VERSION 5.8 ;
BUSBITCHARS "[]" ;
DIVIDERCHAR "/" ;
UNITS
    DATABASE MICRONS 1000 ;
END UNITS

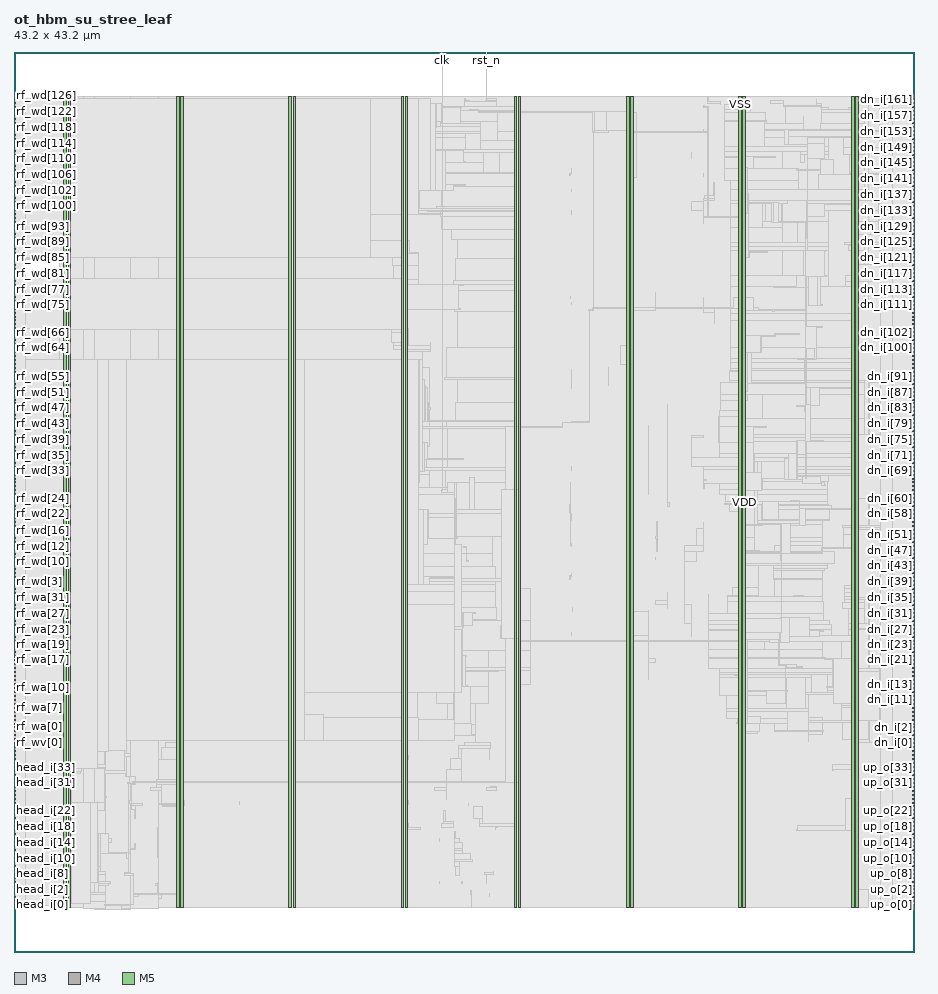
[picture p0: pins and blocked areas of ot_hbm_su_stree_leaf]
MACRO ot_hbm_su_stree_leaf
  FOREIGN ot_hbm_su_stree_leaf 0 0 ;
  CLASS BLOCK ;
  SIZE 43.2 BY 43.2 ;
  PIN clk
    DIRECTION INPUT ;
    USE SIGNAL ;
    PORT
      LAYER M3 ;
        RECT  20.52 43.162 20.538 43.2 ;
    END
  END clk
  PIN dn_i[0]
    DIRECTION INPUT ;
    USE SIGNAL ;
    PORT
      LAYER M4 ;
        RECT  43.116 10.032 43.2 10.056 ;
    END
  END dn_i[0]
  PIN dn_i[100]
    DIRECTION INPUT ;
    USE SIGNAL ;
    PORT
      LAYER M4 ;
        RECT  43.116 28.992 43.2 29.016 ;
    END
  END dn_i[100]
  PIN dn_i[101]
    DIRECTION INPUT ;
    USE SIGNAL ;
    PORT
      LAYER M4 ;
        RECT  43.116 29.184 43.2 29.208 ;
    END
  END dn_i[101]
  PIN dn_i[102]
    DIRECTION INPUT ;
    USE SIGNAL ;
    PORT
      LAYER M4 ;
        RECT  43.116 29.376 43.2 29.4 ;
    END
  END dn_i[102]
  PIN dn_i[103]
    DIRECTION INPUT ;
    USE SIGNAL ;
    PORT
      LAYER M4 ;
        RECT  43.116 29.568 43.2 29.592 ;
    END
  END dn_i[103]
  PIN dn_i[104]
    DIRECTION INPUT ;
    USE SIGNAL ;
    PORT
      LAYER M4 ;
        RECT  43.116 29.76 43.2 29.784 ;
    END
  END dn_i[104]
  PIN dn_i[105]
    DIRECTION INPUT ;
    USE SIGNAL ;
    PORT
      LAYER M4 ;
        RECT  43.116 29.952 43.2 29.976 ;
    END
  END dn_i[105]
  PIN dn_i[106]
    DIRECTION INPUT ;
    USE SIGNAL ;
    PORT
      LAYER M4 ;
        RECT  43.116 30.144 43.2 30.168 ;
    END
  END dn_i[106]
  PIN dn_i[107]
    DIRECTION INPUT ;
    USE SIGNAL ;
    PORT
      LAYER M4 ;
        RECT  43.116 30.336 43.2 30.36 ;
    END
  END dn_i[107]
  PIN dn_i[108]
    DIRECTION INPUT ;
    USE SIGNAL ;
    PORT
      LAYER M4 ;
        RECT  43.116 30.48 43.2 30.504 ;
    END
  END dn_i[108]
  PIN dn_i[109]
    DIRECTION INPUT ;
    USE SIGNAL ;
    PORT
      LAYER M4 ;
        RECT  43.116 30.672 43.2 30.696 ;
    END
  END dn_i[109]
  PIN dn_i[10]
    DIRECTION INPUT ;
    USE SIGNAL ;
    PORT
      LAYER M4 ;
        RECT  43.116 11.904 43.2 11.928 ;
    END
  END dn_i[10]
  PIN dn_i[110]
    DIRECTION INPUT ;
    USE SIGNAL ;
    PORT
      LAYER M4 ;
        RECT  43.116 30.864 43.2 30.888 ;
    END
  END dn_i[110]
  PIN dn_i[111]
    DIRECTION INPUT ;
    USE SIGNAL ;
    PORT
      LAYER M4 ;
        RECT  43.116 31.056 43.2 31.08 ;
    END
  END dn_i[111]
  PIN dn_i[112]
    DIRECTION INPUT ;
    USE SIGNAL ;
    PORT
      LAYER M4 ;
        RECT  43.116 31.248 43.2 31.272 ;
    END
  END dn_i[112]
  PIN dn_i[113]
    DIRECTION INPUT ;
    USE SIGNAL ;
    PORT
      LAYER M4 ;
        RECT  43.116 31.44 43.2 31.464 ;
    END
  END dn_i[113]
  PIN dn_i[114]
    DIRECTION INPUT ;
    USE SIGNAL ;
    PORT
      LAYER M4 ;
        RECT  43.116 31.632 43.2 31.656 ;
    END
  END dn_i[114]
  PIN dn_i[115]
    DIRECTION INPUT ;
    USE SIGNAL ;
    PORT
      LAYER M4 ;
        RECT  43.116 31.824 43.2 31.848 ;
    END
  END dn_i[115]
  PIN dn_i[116]
    DIRECTION INPUT ;
    USE SIGNAL ;
    PORT
      LAYER M4 ;
        RECT  43.116 32.016 43.2 32.04 ;
    END
  END dn_i[116]
  PIN dn_i[117]
    DIRECTION INPUT ;
    USE SIGNAL ;
    PORT
      LAYER M4 ;
        RECT  43.116 32.208 43.2 32.232 ;
    END
  END dn_i[117]
  PIN dn_i[118]
    DIRECTION INPUT ;
    USE SIGNAL ;
    PORT
      LAYER M4 ;
        RECT  43.116 32.4 43.2 32.424 ;
    END
  END dn_i[118]
  PIN dn_i[119]
    DIRECTION INPUT ;
    USE SIGNAL ;
    PORT
      LAYER M4 ;
        RECT  43.116 32.592 43.2 32.616 ;
    END
  END dn_i[119]
  PIN dn_i[11]
    DIRECTION INPUT ;
    USE SIGNAL ;
    PORT
      LAYER M4 ;
        RECT  43.116 12.096 43.2 12.12 ;
    END
  END dn_i[11]
  PIN dn_i[120]
    DIRECTION INPUT ;
    USE SIGNAL ;
    PORT
      LAYER M4 ;
        RECT  43.116 32.784 43.2 32.808 ;
    END
  END dn_i[120]
  PIN dn_i[121]
    DIRECTION INPUT ;
    USE SIGNAL ;
    PORT
      LAYER M4 ;
        RECT  43.116 32.976 43.2 33 ;
    END
  END dn_i[121]
  PIN dn_i[122]
    DIRECTION INPUT ;
    USE SIGNAL ;
    PORT
      LAYER M4 ;
        RECT  43.116 33.168 43.2 33.192 ;
    END
  END dn_i[122]
  PIN dn_i[123]
    DIRECTION INPUT ;
    USE SIGNAL ;
    PORT
      LAYER M4 ;
        RECT  43.116 33.36 43.2 33.384 ;
    END
  END dn_i[123]
  PIN dn_i[124]
    DIRECTION INPUT ;
    USE SIGNAL ;
    PORT
      LAYER M4 ;
        RECT  43.116 33.552 43.2 33.576 ;
    END
  END dn_i[124]
  PIN dn_i[125]
    DIRECTION INPUT ;
    USE SIGNAL ;
    PORT
      LAYER M4 ;
        RECT  43.116 33.744 43.2 33.768 ;
    END
  END dn_i[125]
  PIN dn_i[126]
    DIRECTION INPUT ;
    USE SIGNAL ;
    PORT
      LAYER M4 ;
        RECT  43.116 33.936 43.2 33.96 ;
    END
  END dn_i[126]
  PIN dn_i[127]
    DIRECTION INPUT ;
    USE SIGNAL ;
    PORT
      LAYER M4 ;
        RECT  43.116 34.128 43.2 34.152 ;
    END
  END dn_i[127]
  PIN dn_i[128]
    DIRECTION INPUT ;
    USE SIGNAL ;
    PORT
      LAYER M4 ;
        RECT  43.116 34.272 43.2 34.296 ;
    END
  END dn_i[128]
  PIN dn_i[129]
    DIRECTION INPUT ;
    USE SIGNAL ;
    PORT
      LAYER M4 ;
        RECT  43.116 34.464 43.2 34.488 ;
    END
  END dn_i[129]
  PIN dn_i[12]
    DIRECTION INPUT ;
    USE SIGNAL ;
    PORT
      LAYER M4 ;
        RECT  43.116 12.288 43.2 12.312 ;
    END
  END dn_i[12]
  PIN dn_i[130]
    DIRECTION INPUT ;
    USE SIGNAL ;
    PORT
      LAYER M4 ;
        RECT  43.116 34.656 43.2 34.68 ;
    END
  END dn_i[130]
  PIN dn_i[131]
    DIRECTION INPUT ;
    USE SIGNAL ;
    PORT
      LAYER M4 ;
        RECT  43.116 34.848 43.2 34.872 ;
    END
  END dn_i[131]
  PIN dn_i[132]
    DIRECTION INPUT ;
    USE SIGNAL ;
    PORT
      LAYER M4 ;
        RECT  43.116 35.04 43.2 35.064 ;
    END
  END dn_i[132]
  PIN dn_i[133]
    DIRECTION INPUT ;
    USE SIGNAL ;
    PORT
      LAYER M4 ;
        RECT  43.116 35.232 43.2 35.256 ;
    END
  END dn_i[133]
  PIN dn_i[134]
    DIRECTION INPUT ;
    USE SIGNAL ;
    PORT
      LAYER M4 ;
        RECT  43.116 35.424 43.2 35.448 ;
    END
  END dn_i[134]
  PIN dn_i[135]
    DIRECTION INPUT ;
    USE SIGNAL ;
    PORT
      LAYER M4 ;
        RECT  43.116 35.616 43.2 35.64 ;
    END
  END dn_i[135]
  PIN dn_i[136]
    DIRECTION INPUT ;
    USE SIGNAL ;
    PORT
      LAYER M4 ;
        RECT  43.116 35.808 43.2 35.832 ;
    END
  END dn_i[136]
  PIN dn_i[137]
    DIRECTION INPUT ;
    USE SIGNAL ;
    PORT
      LAYER M4 ;
        RECT  43.116 36 43.2 36.024 ;
    END
  END dn_i[137]
  PIN dn_i[138]
    DIRECTION INPUT ;
    USE SIGNAL ;
    PORT
      LAYER M4 ;
        RECT  43.116 36.192 43.2 36.216 ;
    END
  END dn_i[138]
  PIN dn_i[139]
    DIRECTION INPUT ;
    USE SIGNAL ;
    PORT
      LAYER M4 ;
        RECT  43.116 36.384 43.2 36.408 ;
    END
  END dn_i[139]
  PIN dn_i[13]
    DIRECTION INPUT ;
    USE SIGNAL ;
    PORT
      LAYER M4 ;
        RECT  43.116 12.48 43.2 12.504 ;
    END
  END dn_i[13]
  PIN dn_i[140]
    DIRECTION INPUT ;
    USE SIGNAL ;
    PORT
      LAYER M4 ;
        RECT  43.116 36.576 43.2 36.6 ;
    END
  END dn_i[140]
  PIN dn_i[141]
    DIRECTION INPUT ;
    USE SIGNAL ;
    PORT
      LAYER M4 ;
        RECT  43.116 36.768 43.2 36.792 ;
    END
  END dn_i[141]
  PIN dn_i[142]
    DIRECTION INPUT ;
    USE SIGNAL ;
    PORT
      LAYER M4 ;
        RECT  43.116 36.96 43.2 36.984 ;
    END
  END dn_i[142]
  PIN dn_i[143]
    DIRECTION INPUT ;
    USE SIGNAL ;
    PORT
      LAYER M4 ;
        RECT  43.116 37.152 43.2 37.176 ;
    END
  END dn_i[143]
  PIN dn_i[144]
    DIRECTION INPUT ;
    USE SIGNAL ;
    PORT
      LAYER M4 ;
        RECT  43.116 37.344 43.2 37.368 ;
    END
  END dn_i[144]
  PIN dn_i[145]
    DIRECTION INPUT ;
    USE SIGNAL ;
    PORT
      LAYER M4 ;
        RECT  43.116 37.536 43.2 37.56 ;
    END
  END dn_i[145]
  PIN dn_i[146]
    DIRECTION INPUT ;
    USE SIGNAL ;
    PORT
      LAYER M4 ;
        RECT  43.116 37.728 43.2 37.752 ;
    END
  END dn_i[146]
  PIN dn_i[147]
    DIRECTION INPUT ;
    USE SIGNAL ;
    PORT
      LAYER M4 ;
        RECT  43.116 37.92 43.2 37.944 ;
    END
  END dn_i[147]
  PIN dn_i[148]
    DIRECTION INPUT ;
    USE SIGNAL ;
    PORT
      LAYER M4 ;
        RECT  43.116 38.112 43.2 38.136 ;
    END
  END dn_i[148]
  PIN dn_i[149]
    DIRECTION INPUT ;
    USE SIGNAL ;
    PORT
      LAYER M4 ;
        RECT  43.116 38.256 43.2 38.28 ;
    END
  END dn_i[149]
  PIN dn_i[14]
    DIRECTION INPUT ;
    USE SIGNAL ;
    PORT
      LAYER M4 ;
        RECT  43.116 12.672 43.2 12.696 ;
    END
  END dn_i[14]
  PIN dn_i[150]
    DIRECTION INPUT ;
    USE SIGNAL ;
    PORT
      LAYER M4 ;
        RECT  43.116 38.448 43.2 38.472 ;
    END
  END dn_i[150]
  PIN dn_i[151]
    DIRECTION INPUT ;
    USE SIGNAL ;
    PORT
      LAYER M4 ;
        RECT  43.116 38.64 43.2 38.664 ;
    END
  END dn_i[151]
  PIN dn_i[152]
    DIRECTION INPUT ;
    USE SIGNAL ;
    PORT
      LAYER M4 ;
        RECT  43.116 38.832 43.2 38.856 ;
    END
  END dn_i[152]
  PIN dn_i[153]
    DIRECTION INPUT ;
    USE SIGNAL ;
    PORT
      LAYER M4 ;
        RECT  43.116 39.024 43.2 39.048 ;
    END
  END dn_i[153]
  PIN dn_i[154]
    DIRECTION INPUT ;
    USE SIGNAL ;
    PORT
      LAYER M4 ;
        RECT  43.116 39.216 43.2 39.24 ;
    END
  END dn_i[154]
  PIN dn_i[155]
    DIRECTION INPUT ;
    USE SIGNAL ;
    PORT
      LAYER M4 ;
        RECT  43.116 39.408 43.2 39.432 ;
    END
  END dn_i[155]
  PIN dn_i[156]
    DIRECTION INPUT ;
    USE SIGNAL ;
    PORT
      LAYER M4 ;
        RECT  43.116 39.6 43.2 39.624 ;
    END
  END dn_i[156]
  PIN dn_i[157]
    DIRECTION INPUT ;
    USE SIGNAL ;
    PORT
      LAYER M4 ;
        RECT  43.116 39.792 43.2 39.816 ;
    END
  END dn_i[157]
  PIN dn_i[158]
    DIRECTION INPUT ;
    USE SIGNAL ;
    PORT
      LAYER M4 ;
        RECT  43.116 39.984 43.2 40.008 ;
    END
  END dn_i[158]
  PIN dn_i[159]
    DIRECTION INPUT ;
    USE SIGNAL ;
    PORT
      LAYER M4 ;
        RECT  43.116 40.176 43.2 40.2 ;
    END
  END dn_i[159]
  PIN dn_i[15]
    DIRECTION INPUT ;
    USE SIGNAL ;
    PORT
      LAYER M4 ;
        RECT  43.116 12.864 43.2 12.888 ;
    END
  END dn_i[15]
  PIN dn_i[160]
    DIRECTION INPUT ;
    USE SIGNAL ;
    PORT
      LAYER M4 ;
        RECT  43.116 40.368 43.2 40.392 ;
    END
  END dn_i[160]
  PIN dn_i[161]
    DIRECTION INPUT ;
    USE SIGNAL ;
    PORT
      LAYER M4 ;
        RECT  43.116 40.56 43.2 40.584 ;
    END
  END dn_i[161]
  PIN dn_i[162]
    DIRECTION INPUT ;
    USE SIGNAL ;
    PORT
      LAYER M4 ;
        RECT  43.116 40.752 43.2 40.776 ;
    END
  END dn_i[162]
  PIN dn_i[163]
    DIRECTION INPUT ;
    USE SIGNAL ;
    PORT
      LAYER M4 ;
        RECT  43.116 40.944 43.2 40.968 ;
    END
  END dn_i[163]
  PIN dn_i[16]
    DIRECTION INPUT ;
    USE SIGNAL ;
    PORT
      LAYER M4 ;
        RECT  43.116 13.056 43.2 13.08 ;
    END
  END dn_i[16]
  PIN dn_i[17]
    DIRECTION INPUT ;
    USE SIGNAL ;
    PORT
      LAYER M4 ;
        RECT  43.116 13.248 43.2 13.272 ;
    END
  END dn_i[17]
  PIN dn_i[18]
    DIRECTION INPUT ;
    USE SIGNAL ;
    PORT
      LAYER M4 ;
        RECT  43.116 13.44 43.2 13.464 ;
    END
  END dn_i[18]
  PIN dn_i[19]
    DIRECTION INPUT ;
    USE SIGNAL ;
    PORT
      LAYER M4 ;
        RECT  43.116 13.632 43.2 13.656 ;
    END
  END dn_i[19]
  PIN dn_i[1]
    DIRECTION INPUT ;
    USE SIGNAL ;
    PORT
      LAYER M4 ;
        RECT  43.116 10.224 43.2 10.248 ;
    END
  END dn_i[1]
  PIN dn_i[20]
    DIRECTION INPUT ;
    USE SIGNAL ;
    PORT
      LAYER M4 ;
        RECT  43.116 13.824 43.2 13.848 ;
    END
  END dn_i[20]
  PIN dn_i[21]
    DIRECTION INPUT ;
    USE SIGNAL ;
    PORT
      LAYER M4 ;
        RECT  43.116 14.016 43.2 14.04 ;
    END
  END dn_i[21]
  PIN dn_i[22]
    DIRECTION INPUT ;
    USE SIGNAL ;
    PORT
      LAYER M4 ;
        RECT  43.116 14.208 43.2 14.232 ;
    END
  END dn_i[22]
  PIN dn_i[23]
    DIRECTION INPUT ;
    USE SIGNAL ;
    PORT
      LAYER M4 ;
        RECT  43.116 14.4 43.2 14.424 ;
    END
  END dn_i[23]
  PIN dn_i[24]
    DIRECTION INPUT ;
    USE SIGNAL ;
    PORT
      LAYER M4 ;
        RECT  43.116 14.592 43.2 14.616 ;
    END
  END dn_i[24]
  PIN dn_i[25]
    DIRECTION INPUT ;
    USE SIGNAL ;
    PORT
      LAYER M4 ;
        RECT  43.116 14.784 43.2 14.808 ;
    END
  END dn_i[25]
  PIN dn_i[26]
    DIRECTION INPUT ;
    USE SIGNAL ;
    PORT
      LAYER M4 ;
        RECT  43.116 14.928 43.2 14.952 ;
    END
  END dn_i[26]
  PIN dn_i[27]
    DIRECTION INPUT ;
    USE SIGNAL ;
    PORT
      LAYER M4 ;
        RECT  43.116 15.12 43.2 15.144 ;
    END
  END dn_i[27]
  PIN dn_i[28]
    DIRECTION INPUT ;
    USE SIGNAL ;
    PORT
      LAYER M4 ;
        RECT  43.116 15.312 43.2 15.336 ;
    END
  END dn_i[28]
  PIN dn_i[29]
    DIRECTION INPUT ;
    USE SIGNAL ;
    PORT
      LAYER M4 ;
        RECT  43.116 15.504 43.2 15.528 ;
    END
  END dn_i[29]
  PIN dn_i[2]
    DIRECTION INPUT ;
    USE SIGNAL ;
    PORT
      LAYER M4 ;
        RECT  43.116 10.416 43.2 10.44 ;
    END
  END dn_i[2]
  PIN dn_i[30]
    DIRECTION INPUT ;
    USE SIGNAL ;
    PORT
      LAYER M4 ;
        RECT  43.116 15.696 43.2 15.72 ;
    END
  END dn_i[30]
  PIN dn_i[31]
    DIRECTION INPUT ;
    USE SIGNAL ;
    PORT
      LAYER M4 ;
        RECT  43.116 15.888 43.2 15.912 ;
    END
  END dn_i[31]
  PIN dn_i[32]
    DIRECTION INPUT ;
    USE SIGNAL ;
    PORT
      LAYER M4 ;
        RECT  43.116 16.08 43.2 16.104 ;
    END
  END dn_i[32]
  PIN dn_i[33]
    DIRECTION INPUT ;
    USE SIGNAL ;
    PORT
      LAYER M4 ;
        RECT  43.116 16.272 43.2 16.296 ;
    END
  END dn_i[33]
  PIN dn_i[34]
    DIRECTION INPUT ;
    USE SIGNAL ;
    PORT
      LAYER M4 ;
        RECT  43.116 16.464 43.2 16.488 ;
    END
  END dn_i[34]
  PIN dn_i[35]
    DIRECTION INPUT ;
    USE SIGNAL ;
    PORT
      LAYER M4 ;
        RECT  43.116 16.656 43.2 16.68 ;
    END
  END dn_i[35]
  PIN dn_i[36]
    DIRECTION INPUT ;
    USE SIGNAL ;
    PORT
      LAYER M4 ;
        RECT  43.116 16.848 43.2 16.872 ;
    END
  END dn_i[36]
  PIN dn_i[37]
    DIRECTION INPUT ;
    USE SIGNAL ;
    PORT
      LAYER M4 ;
        RECT  43.116 17.04 43.2 17.064 ;
    END
  END dn_i[37]
  PIN dn_i[38]
    DIRECTION INPUT ;
    USE SIGNAL ;
    PORT
      LAYER M4 ;
        RECT  43.116 17.232 43.2 17.256 ;
    END
  END dn_i[38]
  PIN dn_i[39]
    DIRECTION INPUT ;
    USE SIGNAL ;
    PORT
      LAYER M4 ;
        RECT  43.116 17.424 43.2 17.448 ;
    END
  END dn_i[39]
  PIN dn_i[3]
    DIRECTION INPUT ;
    USE SIGNAL ;
    PORT
      LAYER M4 ;
        RECT  43.116 10.608 43.2 10.632 ;
    END
  END dn_i[3]
  PIN dn_i[40]
    DIRECTION INPUT ;
    USE SIGNAL ;
    PORT
      LAYER M4 ;
        RECT  43.116 17.616 43.2 17.64 ;
    END
  END dn_i[40]
  PIN dn_i[41]
    DIRECTION INPUT ;
    USE SIGNAL ;
    PORT
      LAYER M4 ;
        RECT  43.116 17.808 43.2 17.832 ;
    END
  END dn_i[41]
  PIN dn_i[42]
    DIRECTION INPUT ;
    USE SIGNAL ;
    PORT
      LAYER M4 ;
        RECT  43.116 18 43.2 18.024 ;
    END
  END dn_i[42]
  PIN dn_i[43]
    DIRECTION INPUT ;
    USE SIGNAL ;
    PORT
      LAYER M4 ;
        RECT  43.116 18.192 43.2 18.216 ;
    END
  END dn_i[43]
  PIN dn_i[44]
    DIRECTION INPUT ;
    USE SIGNAL ;
    PORT
      LAYER M4 ;
        RECT  43.116 18.384 43.2 18.408 ;
    END
  END dn_i[44]
  PIN dn_i[45]
    DIRECTION INPUT ;
    USE SIGNAL ;
    PORT
      LAYER M4 ;
        RECT  43.116 18.576 43.2 18.6 ;
    END
  END dn_i[45]
  PIN dn_i[46]
    DIRECTION INPUT ;
    USE SIGNAL ;
    PORT
      LAYER M4 ;
        RECT  43.116 18.72 43.2 18.744 ;
    END
  END dn_i[46]
  PIN dn_i[47]
    DIRECTION INPUT ;
    USE SIGNAL ;
    PORT
      LAYER M4 ;
        RECT  43.116 18.912 43.2 18.936 ;
    END
  END dn_i[47]
  PIN dn_i[48]
    DIRECTION INPUT ;
    USE SIGNAL ;
    PORT
      LAYER M4 ;
        RECT  43.116 19.104 43.2 19.128 ;
    END
  END dn_i[48]
  PIN dn_i[49]
    DIRECTION INPUT ;
    USE SIGNAL ;
    PORT
      LAYER M4 ;
        RECT  43.116 19.296 43.2 19.32 ;
    END
  END dn_i[49]
  PIN dn_i[4]
    DIRECTION INPUT ;
    USE SIGNAL ;
    PORT
      LAYER M4 ;
        RECT  43.116 10.8 43.2 10.824 ;
    END
  END dn_i[4]
  PIN dn_i[50]
    DIRECTION INPUT ;
    USE SIGNAL ;
    PORT
      LAYER M4 ;
        RECT  43.116 19.488 43.2 19.512 ;
    END
  END dn_i[50]
  PIN dn_i[51]
    DIRECTION INPUT ;
    USE SIGNAL ;
    PORT
      LAYER M4 ;
        RECT  43.116 19.68 43.2 19.704 ;
    END
  END dn_i[51]
  PIN dn_i[52]
    DIRECTION INPUT ;
    USE SIGNAL ;
    PORT
      LAYER M4 ;
        RECT  43.116 19.872 43.2 19.896 ;
    END
  END dn_i[52]
  PIN dn_i[53]
    DIRECTION INPUT ;
    USE SIGNAL ;
    PORT
      LAYER M4 ;
        RECT  43.116 20.064 43.2 20.088 ;
    END
  END dn_i[53]
  PIN dn_i[54]
    DIRECTION INPUT ;
    USE SIGNAL ;
    PORT
      LAYER M4 ;
        RECT  43.116 20.256 43.2 20.28 ;
    END
  END dn_i[54]
  PIN dn_i[55]
    DIRECTION INPUT ;
    USE SIGNAL ;
    PORT
      LAYER M4 ;
        RECT  43.116 20.448 43.2 20.472 ;
    END
  END dn_i[55]
  PIN dn_i[56]
    DIRECTION INPUT ;
    USE SIGNAL ;
    PORT
      LAYER M4 ;
        RECT  43.116 20.64 43.2 20.664 ;
    END
  END dn_i[56]
  PIN dn_i[57]
    DIRECTION INPUT ;
    USE SIGNAL ;
    PORT
      LAYER M4 ;
        RECT  43.116 20.832 43.2 20.856 ;
    END
  END dn_i[57]
  PIN dn_i[58]
    DIRECTION INPUT ;
    USE SIGNAL ;
    PORT
      LAYER M4 ;
        RECT  43.116 21.024 43.2 21.048 ;
    END
  END dn_i[58]
  PIN dn_i[59]
    DIRECTION INPUT ;
    USE SIGNAL ;
    PORT
      LAYER M4 ;
        RECT  43.116 21.216 43.2 21.24 ;
    END
  END dn_i[59]
  PIN dn_i[5]
    DIRECTION INPUT ;
    USE SIGNAL ;
    PORT
      LAYER M4 ;
        RECT  43.116 10.944 43.2 10.968 ;
    END
  END dn_i[5]
  PIN dn_i[60]
    DIRECTION INPUT ;
    USE SIGNAL ;
    PORT
      LAYER M4 ;
        RECT  43.116 21.408 43.2 21.432 ;
    END
  END dn_i[60]
  PIN dn_i[61]
    DIRECTION INPUT ;
    USE SIGNAL ;
    PORT
      LAYER M4 ;
        RECT  43.116 21.6 43.2 21.624 ;
    END
  END dn_i[61]
  PIN dn_i[62]
    DIRECTION INPUT ;
    USE SIGNAL ;
    PORT
      LAYER M4 ;
        RECT  43.116 21.792 43.2 21.816 ;
    END
  END dn_i[62]
  PIN dn_i[63]
    DIRECTION INPUT ;
    USE SIGNAL ;
    PORT
      LAYER M4 ;
        RECT  43.116 21.984 43.2 22.008 ;
    END
  END dn_i[63]
  PIN dn_i[64]
    DIRECTION INPUT ;
    USE SIGNAL ;
    PORT
      LAYER M4 ;
        RECT  43.116 22.176 43.2 22.2 ;
    END
  END dn_i[64]
  PIN dn_i[65]
    DIRECTION INPUT ;
    USE SIGNAL ;
    PORT
      LAYER M4 ;
        RECT  43.116 22.368 43.2 22.392 ;
    END
  END dn_i[65]
  PIN dn_i[66]
    DIRECTION INPUT ;
    USE SIGNAL ;
    PORT
      LAYER M4 ;
        RECT  43.116 22.56 43.2 22.584 ;
    END
  END dn_i[66]
  PIN dn_i[67]
    DIRECTION INPUT ;
    USE SIGNAL ;
    PORT
      LAYER M4 ;
        RECT  43.116 22.704 43.2 22.728 ;
    END
  END dn_i[67]
  PIN dn_i[68]
    DIRECTION INPUT ;
    USE SIGNAL ;
    PORT
      LAYER M4 ;
        RECT  43.116 22.896 43.2 22.92 ;
    END
  END dn_i[68]
  PIN dn_i[69]
    DIRECTION INPUT ;
    USE SIGNAL ;
    PORT
      LAYER M4 ;
        RECT  43.116 23.088 43.2 23.112 ;
    END
  END dn_i[69]
  PIN dn_i[6]
    DIRECTION INPUT ;
    USE SIGNAL ;
    PORT
      LAYER M4 ;
        RECT  43.116 11.136 43.2 11.16 ;
    END
  END dn_i[6]
  PIN dn_i[70]
    DIRECTION INPUT ;
    USE SIGNAL ;
    PORT
      LAYER M4 ;
        RECT  43.116 23.28 43.2 23.304 ;
    END
  END dn_i[70]
  PIN dn_i[71]
    DIRECTION INPUT ;
    USE SIGNAL ;
    PORT
      LAYER M4 ;
        RECT  43.116 23.472 43.2 23.496 ;
    END
  END dn_i[71]
  PIN dn_i[72]
    DIRECTION INPUT ;
    USE SIGNAL ;
    PORT
      LAYER M4 ;
        RECT  43.116 23.664 43.2 23.688 ;
    END
  END dn_i[72]
  PIN dn_i[73]
    DIRECTION INPUT ;
    USE SIGNAL ;
    PORT
      LAYER M4 ;
        RECT  43.116 23.856 43.2 23.88 ;
    END
  END dn_i[73]
  PIN dn_i[74]
    DIRECTION INPUT ;
    USE SIGNAL ;
    PORT
      LAYER M4 ;
        RECT  43.116 24.048 43.2 24.072 ;
    END
  END dn_i[74]
  PIN dn_i[75]
    DIRECTION INPUT ;
    USE SIGNAL ;
    PORT
      LAYER M4 ;
        RECT  43.116 24.24 43.2 24.264 ;
    END
  END dn_i[75]
  PIN dn_i[76]
    DIRECTION INPUT ;
    USE SIGNAL ;
    PORT
      LAYER M4 ;
        RECT  43.116 24.432 43.2 24.456 ;
    END
  END dn_i[76]
  PIN dn_i[77]
    DIRECTION INPUT ;
    USE SIGNAL ;
    PORT
      LAYER M4 ;
        RECT  43.116 24.624 43.2 24.648 ;
    END
  END dn_i[77]
  PIN dn_i[78]
    DIRECTION INPUT ;
    USE SIGNAL ;
    PORT
      LAYER M4 ;
        RECT  43.116 24.816 43.2 24.84 ;
    END
  END dn_i[78]
  PIN dn_i[79]
    DIRECTION INPUT ;
    USE SIGNAL ;
    PORT
      LAYER M4 ;
        RECT  43.116 25.008 43.2 25.032 ;
    END
  END dn_i[79]
  PIN dn_i[7]
    DIRECTION INPUT ;
    USE SIGNAL ;
    PORT
      LAYER M4 ;
        RECT  43.116 11.328 43.2 11.352 ;
    END
  END dn_i[7]
  PIN dn_i[80]
    DIRECTION INPUT ;
    USE SIGNAL ;
    PORT
      LAYER M4 ;
        RECT  43.116 25.2 43.2 25.224 ;
    END
  END dn_i[80]
  PIN dn_i[81]
    DIRECTION INPUT ;
    USE SIGNAL ;
    PORT
      LAYER M4 ;
        RECT  43.116 25.392 43.2 25.416 ;
    END
  END dn_i[81]
  PIN dn_i[82]
    DIRECTION INPUT ;
    USE SIGNAL ;
    PORT
      LAYER M4 ;
        RECT  43.116 25.584 43.2 25.608 ;
    END
  END dn_i[82]
  PIN dn_i[83]
    DIRECTION INPUT ;
    USE SIGNAL ;
    PORT
      LAYER M4 ;
        RECT  43.116 25.776 43.2 25.8 ;
    END
  END dn_i[83]
  PIN dn_i[84]
    DIRECTION INPUT ;
    USE SIGNAL ;
    PORT
      LAYER M4 ;
        RECT  43.116 25.968 43.2 25.992 ;
    END
  END dn_i[84]
  PIN dn_i[85]
    DIRECTION INPUT ;
    USE SIGNAL ;
    PORT
      LAYER M4 ;
        RECT  43.116 26.16 43.2 26.184 ;
    END
  END dn_i[85]
  PIN dn_i[86]
    DIRECTION INPUT ;
    USE SIGNAL ;
    PORT
      LAYER M4 ;
        RECT  43.116 26.352 43.2 26.376 ;
    END
  END dn_i[86]
  PIN dn_i[87]
    DIRECTION INPUT ;
    USE SIGNAL ;
    PORT
      LAYER M4 ;
        RECT  43.116 26.496 43.2 26.52 ;
    END
  END dn_i[87]
  PIN dn_i[88]
    DIRECTION INPUT ;
    USE SIGNAL ;
    PORT
      LAYER M4 ;
        RECT  43.116 26.688 43.2 26.712 ;
    END
  END dn_i[88]
  PIN dn_i[89]
    DIRECTION INPUT ;
    USE SIGNAL ;
    PORT
      LAYER M4 ;
        RECT  43.116 26.88 43.2 26.904 ;
    END
  END dn_i[89]
  PIN dn_i[8]
    DIRECTION INPUT ;
    USE SIGNAL ;
    PORT
      LAYER M4 ;
        RECT  43.116 11.52 43.2 11.544 ;
    END
  END dn_i[8]
  PIN dn_i[90]
    DIRECTION INPUT ;
    USE SIGNAL ;
    PORT
      LAYER M4 ;
        RECT  43.116 27.072 43.2 27.096 ;
    END
  END dn_i[90]
  PIN dn_i[91]
    DIRECTION INPUT ;
    USE SIGNAL ;
    PORT
      LAYER M4 ;
        RECT  43.116 27.264 43.2 27.288 ;
    END
  END dn_i[91]
  PIN dn_i[92]
    DIRECTION INPUT ;
    USE SIGNAL ;
    PORT
      LAYER M4 ;
        RECT  43.116 27.456 43.2 27.48 ;
    END
  END dn_i[92]
  PIN dn_i[93]
    DIRECTION INPUT ;
    USE SIGNAL ;
    PORT
      LAYER M4 ;
        RECT  43.116 27.648 43.2 27.672 ;
    END
  END dn_i[93]
  PIN dn_i[94]
    DIRECTION INPUT ;
    USE SIGNAL ;
    PORT
      LAYER M4 ;
        RECT  43.116 27.84 43.2 27.864 ;
    END
  END dn_i[94]
  PIN dn_i[95]
    DIRECTION INPUT ;
    USE SIGNAL ;
    PORT
      LAYER M4 ;
        RECT  43.116 28.032 43.2 28.056 ;
    END
  END dn_i[95]
  PIN dn_i[96]
    DIRECTION INPUT ;
    USE SIGNAL ;
    PORT
      LAYER M4 ;
        RECT  43.116 28.224 43.2 28.248 ;
    END
  END dn_i[96]
  PIN dn_i[97]
    DIRECTION INPUT ;
    USE SIGNAL ;
    PORT
      LAYER M4 ;
        RECT  43.116 28.416 43.2 28.44 ;
    END
  END dn_i[97]
  PIN dn_i[98]
    DIRECTION INPUT ;
    USE SIGNAL ;
    PORT
      LAYER M4 ;
        RECT  43.116 28.608 43.2 28.632 ;
    END
  END dn_i[98]
  PIN dn_i[99]
    DIRECTION INPUT ;
    USE SIGNAL ;
    PORT
      LAYER M4 ;
        RECT  43.116 28.8 43.2 28.824 ;
    END
  END dn_i[99]
  PIN dn_i[9]
    DIRECTION INPUT ;
    USE SIGNAL ;
    PORT
      LAYER M4 ;
        RECT  43.116 11.712 43.2 11.736 ;
    END
  END dn_i[9]
  PIN head_i[0]
    DIRECTION INPUT ;
    USE SIGNAL ;
    PORT
      LAYER M4 ;
        RECT  0 2.256 0.084 2.28 ;
    END
  END head_i[0]
  PIN head_i[10]
    DIRECTION INPUT ;
    USE SIGNAL ;
    PORT
      LAYER M4 ;
        RECT  0 4.128 0.084 4.152 ;
    END
  END head_i[10]
  PIN head_i[11]
    DIRECTION INPUT ;
    USE SIGNAL ;
    PORT
      LAYER M4 ;
        RECT  0 4.32 0.084 4.344 ;
    END
  END head_i[11]
  PIN head_i[12]
    DIRECTION INPUT ;
    USE SIGNAL ;
    PORT
      LAYER M4 ;
        RECT  0 4.512 0.084 4.536 ;
    END
  END head_i[12]
  PIN head_i[13]
    DIRECTION INPUT ;
    USE SIGNAL ;
    PORT
      LAYER M4 ;
        RECT  0 4.704 0.084 4.728 ;
    END
  END head_i[13]
  PIN head_i[14]
    DIRECTION INPUT ;
    USE SIGNAL ;
    PORT
      LAYER M4 ;
        RECT  0 4.896 0.084 4.92 ;
    END
  END head_i[14]
  PIN head_i[15]
    DIRECTION INPUT ;
    USE SIGNAL ;
    PORT
      LAYER M4 ;
        RECT  0 5.088 0.084 5.112 ;
    END
  END head_i[15]
  PIN head_i[16]
    DIRECTION INPUT ;
    USE SIGNAL ;
    PORT
      LAYER M4 ;
        RECT  0 5.28 0.084 5.304 ;
    END
  END head_i[16]
  PIN head_i[17]
    DIRECTION INPUT ;
    USE SIGNAL ;
    PORT
      LAYER M4 ;
        RECT  0 5.472 0.084 5.496 ;
    END
  END head_i[17]
  PIN head_i[18]
    DIRECTION INPUT ;
    USE SIGNAL ;
    PORT
      LAYER M4 ;
        RECT  0 5.664 0.084 5.688 ;
    END
  END head_i[18]
  PIN head_i[19]
    DIRECTION INPUT ;
    USE SIGNAL ;
    PORT
      LAYER M4 ;
        RECT  0 5.856 0.084 5.88 ;
    END
  END head_i[19]
  PIN head_i[1]
    DIRECTION INPUT ;
    USE SIGNAL ;
    PORT
      LAYER M4 ;
        RECT  0 2.448 0.084 2.472 ;
    END
  END head_i[1]
  PIN head_i[20]
    DIRECTION INPUT ;
    USE SIGNAL ;
    PORT
      LAYER M4 ;
        RECT  0 6.048 0.084 6.072 ;
    END
  END head_i[20]
  PIN head_i[21]
    DIRECTION INPUT ;
    USE SIGNAL ;
    PORT
      LAYER M4 ;
        RECT  0 6.24 0.084 6.264 ;
    END
  END head_i[21]
  PIN head_i[22]
    DIRECTION INPUT ;
    USE SIGNAL ;
    PORT
      LAYER M4 ;
        RECT  0 6.432 0.084 6.456 ;
    END
  END head_i[22]
  PIN head_i[23]
    DIRECTION INPUT ;
    USE SIGNAL ;
    PORT
      LAYER M4 ;
        RECT  0 6.624 0.084 6.648 ;
    END
  END head_i[23]
  PIN head_i[24]
    DIRECTION INPUT ;
    USE SIGNAL ;
    PORT
      LAYER M4 ;
        RECT  0 6.816 0.084 6.84 ;
    END
  END head_i[24]
  PIN head_i[25]
    DIRECTION INPUT ;
    USE SIGNAL ;
    PORT
      LAYER M4 ;
        RECT  0 7.008 0.084 7.032 ;
    END
  END head_i[25]
  PIN head_i[26]
    DIRECTION INPUT ;
    USE SIGNAL ;
    PORT
      LAYER M4 ;
        RECT  0 7.152 0.084 7.176 ;
    END
  END head_i[26]
  PIN head_i[27]
    DIRECTION INPUT ;
    USE SIGNAL ;
    PORT
      LAYER M4 ;
        RECT  0 7.344 0.084 7.368 ;
    END
  END head_i[27]
  PIN head_i[28]
    DIRECTION INPUT ;
    USE SIGNAL ;
    PORT
      LAYER M4 ;
        RECT  0 7.536 0.084 7.56 ;
    END
  END head_i[28]
  PIN head_i[29]
    DIRECTION INPUT ;
    USE SIGNAL ;
    PORT
      LAYER M4 ;
        RECT  0 7.728 0.084 7.752 ;
    END
  END head_i[29]
  PIN head_i[2]
    DIRECTION INPUT ;
    USE SIGNAL ;
    PORT
      LAYER M4 ;
        RECT  0 2.64 0.084 2.664 ;
    END
  END head_i[2]
  PIN head_i[30]
    DIRECTION INPUT ;
    USE SIGNAL ;
    PORT
      LAYER M4 ;
        RECT  0 7.92 0.084 7.944 ;
    END
  END head_i[30]
  PIN head_i[31]
    DIRECTION INPUT ;
    USE SIGNAL ;
    PORT
      LAYER M4 ;
        RECT  0 8.112 0.084 8.136 ;
    END
  END head_i[31]
  PIN head_i[32]
    DIRECTION INPUT ;
    USE SIGNAL ;
    PORT
      LAYER M4 ;
        RECT  0 8.304 0.084 8.328 ;
    END
  END head_i[32]
  PIN head_i[33]
    DIRECTION INPUT ;
    USE SIGNAL ;
    PORT
      LAYER M4 ;
        RECT  0 8.496 0.084 8.52 ;
    END
  END head_i[33]
  PIN head_i[34]
    DIRECTION INPUT ;
    USE SIGNAL ;
    PORT
      LAYER M4 ;
        RECT  0 8.688 0.084 8.712 ;
    END
  END head_i[34]
  PIN head_i[35]
    DIRECTION INPUT ;
    USE SIGNAL ;
    PORT
      LAYER M4 ;
        RECT  0 8.88 0.084 8.904 ;
    END
  END head_i[35]
  PIN head_i[36]
    DIRECTION INPUT ;
    USE SIGNAL ;
    PORT
      LAYER M4 ;
        RECT  0 9.072 0.084 9.096 ;
    END
  END head_i[36]
  PIN head_i[37]
    DIRECTION INPUT ;
    USE SIGNAL ;
    PORT
      LAYER M4 ;
        RECT  0 9.264 0.084 9.288 ;
    END
  END head_i[37]
  PIN head_i[38]
    DIRECTION INPUT ;
    USE SIGNAL ;
    PORT
      LAYER M4 ;
        RECT  0 9.456 0.084 9.48 ;
    END
  END head_i[38]
  PIN head_i[39]
    DIRECTION INPUT ;
    USE SIGNAL ;
    PORT
      LAYER M4 ;
        RECT  0 9.648 0.084 9.672 ;
    END
  END head_i[39]
  PIN head_i[3]
    DIRECTION INPUT ;
    USE SIGNAL ;
    PORT
      LAYER M4 ;
        RECT  0 2.832 0.084 2.856 ;
    END
  END head_i[3]
  PIN head_i[40]
    DIRECTION INPUT ;
    USE SIGNAL ;
    PORT
      LAYER M4 ;
        RECT  0 9.84 0.084 9.864 ;
    END
  END head_i[40]
  PIN head_i[4]
    DIRECTION INPUT ;
    USE SIGNAL ;
    PORT
      LAYER M4 ;
        RECT  0 3.024 0.084 3.048 ;
    END
  END head_i[4]
  PIN head_i[5]
    DIRECTION INPUT ;
    USE SIGNAL ;
    PORT
      LAYER M4 ;
        RECT  0 3.168 0.084 3.192 ;
    END
  END head_i[5]
  PIN head_i[6]
    DIRECTION INPUT ;
    USE SIGNAL ;
    PORT
      LAYER M4 ;
        RECT  0 3.36 0.084 3.384 ;
    END
  END head_i[6]
  PIN head_i[7]
    DIRECTION INPUT ;
    USE SIGNAL ;
    PORT
      LAYER M4 ;
        RECT  0 3.552 0.084 3.576 ;
    END
  END head_i[7]
  PIN head_i[8]
    DIRECTION INPUT ;
    USE SIGNAL ;
    PORT
      LAYER M4 ;
        RECT  0 3.744 0.084 3.768 ;
    END
  END head_i[8]
  PIN head_i[9]
    DIRECTION INPUT ;
    USE SIGNAL ;
    PORT
      LAYER M4 ;
        RECT  0 3.936 0.084 3.96 ;
    END
  END head_i[9]
  PIN rf_wa[0]
    DIRECTION OUTPUT ;
    USE SIGNAL ;
    PORT
      LAYER M4 ;
        RECT  0 10.8 0.084 10.824 ;
    END
  END rf_wa[0]
  PIN rf_wa[10]
    DIRECTION OUTPUT ;
    USE SIGNAL ;
    PORT
      LAYER M4 ;
        RECT  0 12.672 0.084 12.696 ;
    END
  END rf_wa[10]
  PIN rf_wa[11]
    DIRECTION OUTPUT ;
    USE SIGNAL ;
    PORT
      LAYER M4 ;
        RECT  0 12.864 0.084 12.888 ;
    END
  END rf_wa[11]
  PIN rf_wa[12]
    DIRECTION OUTPUT ;
    USE SIGNAL ;
    PORT
      LAYER M4 ;
        RECT  0 13.056 0.084 13.08 ;
    END
  END rf_wa[12]
  PIN rf_wa[13]
    DIRECTION OUTPUT ;
    USE SIGNAL ;
    PORT
      LAYER M4 ;
        RECT  0 13.248 0.084 13.272 ;
    END
  END rf_wa[13]
  PIN rf_wa[14]
    DIRECTION OUTPUT ;
    USE SIGNAL ;
    PORT
      LAYER M4 ;
        RECT  0 13.44 0.084 13.464 ;
    END
  END rf_wa[14]
  PIN rf_wa[15]
    DIRECTION OUTPUT ;
    USE SIGNAL ;
    PORT
      LAYER M4 ;
        RECT  0 13.632 0.084 13.656 ;
    END
  END rf_wa[15]
  PIN rf_wa[16]
    DIRECTION OUTPUT ;
    USE SIGNAL ;
    PORT
      LAYER M4 ;
        RECT  0 13.824 0.084 13.848 ;
    END
  END rf_wa[16]
  PIN rf_wa[17]
    DIRECTION OUTPUT ;
    USE SIGNAL ;
    PORT
      LAYER M4 ;
        RECT  0 14.016 0.084 14.04 ;
    END
  END rf_wa[17]
  PIN rf_wa[18]
    DIRECTION OUTPUT ;
    USE SIGNAL ;
    PORT
      LAYER M4 ;
        RECT  0 14.208 0.084 14.232 ;
    END
  END rf_wa[18]
  PIN rf_wa[19]
    DIRECTION OUTPUT ;
    USE SIGNAL ;
    PORT
      LAYER M4 ;
        RECT  0 14.4 0.084 14.424 ;
    END
  END rf_wa[19]
  PIN rf_wa[1]
    DIRECTION OUTPUT ;
    USE SIGNAL ;
    PORT
      LAYER M4 ;
        RECT  0 10.944 0.084 10.968 ;
    END
  END rf_wa[1]
  PIN rf_wa[20]
    DIRECTION OUTPUT ;
    USE SIGNAL ;
    PORT
      LAYER M4 ;
        RECT  0 14.592 0.084 14.616 ;
    END
  END rf_wa[20]
  PIN rf_wa[21]
    DIRECTION OUTPUT ;
    USE SIGNAL ;
    PORT
      LAYER M4 ;
        RECT  0 14.784 0.084 14.808 ;
    END
  END rf_wa[21]
  PIN rf_wa[22]
    DIRECTION OUTPUT ;
    USE SIGNAL ;
    PORT
      LAYER M4 ;
        RECT  0 14.928 0.084 14.952 ;
    END
  END rf_wa[22]
  PIN rf_wa[23]
    DIRECTION OUTPUT ;
    USE SIGNAL ;
    PORT
      LAYER M4 ;
        RECT  0 15.12 0.084 15.144 ;
    END
  END rf_wa[23]
  PIN rf_wa[24]
    DIRECTION OUTPUT ;
    USE SIGNAL ;
    PORT
      LAYER M4 ;
        RECT  0 15.312 0.084 15.336 ;
    END
  END rf_wa[24]
  PIN rf_wa[25]
    DIRECTION OUTPUT ;
    USE SIGNAL ;
    PORT
      LAYER M4 ;
        RECT  0 15.504 0.084 15.528 ;
    END
  END rf_wa[25]
  PIN rf_wa[26]
    DIRECTION OUTPUT ;
    USE SIGNAL ;
    PORT
      LAYER M4 ;
        RECT  0 15.696 0.084 15.72 ;
    END
  END rf_wa[26]
  PIN rf_wa[27]
    DIRECTION OUTPUT ;
    USE SIGNAL ;
    PORT
      LAYER M4 ;
        RECT  0 15.888 0.084 15.912 ;
    END
  END rf_wa[27]
  PIN rf_wa[28]
    DIRECTION OUTPUT ;
    USE SIGNAL ;
    PORT
      LAYER M4 ;
        RECT  0 16.08 0.084 16.104 ;
    END
  END rf_wa[28]
  PIN rf_wa[29]
    DIRECTION OUTPUT ;
    USE SIGNAL ;
    PORT
      LAYER M4 ;
        RECT  0 16.272 0.084 16.296 ;
    END
  END rf_wa[29]
  PIN rf_wa[2]
    DIRECTION OUTPUT ;
    USE SIGNAL ;
    PORT
      LAYER M4 ;
        RECT  0 11.136 0.084 11.16 ;
    END
  END rf_wa[2]
  PIN rf_wa[30]
    DIRECTION OUTPUT ;
    USE SIGNAL ;
    PORT
      LAYER M4 ;
        RECT  0 16.464 0.084 16.488 ;
    END
  END rf_wa[30]
  PIN rf_wa[31]
    DIRECTION OUTPUT ;
    USE SIGNAL ;
    PORT
      LAYER M4 ;
        RECT  0 16.656 0.084 16.68 ;
    END
  END rf_wa[31]
  PIN rf_wa[3]
    DIRECTION OUTPUT ;
    USE SIGNAL ;
    PORT
      LAYER M4 ;
        RECT  0 11.328 0.084 11.352 ;
    END
  END rf_wa[3]
  PIN rf_wa[4]
    DIRECTION OUTPUT ;
    USE SIGNAL ;
    PORT
      LAYER M4 ;
        RECT  0 11.52 0.084 11.544 ;
    END
  END rf_wa[4]
  PIN rf_wa[5]
    DIRECTION OUTPUT ;
    USE SIGNAL ;
    PORT
      LAYER M4 ;
        RECT  0 11.712 0.084 11.736 ;
    END
  END rf_wa[5]
  PIN rf_wa[6]
    DIRECTION OUTPUT ;
    USE SIGNAL ;
    PORT
      LAYER M4 ;
        RECT  0 11.904 0.084 11.928 ;
    END
  END rf_wa[6]
  PIN rf_wa[7]
    DIRECTION OUTPUT ;
    USE SIGNAL ;
    PORT
      LAYER M4 ;
        RECT  0 12.096 0.084 12.12 ;
    END
  END rf_wa[7]
  PIN rf_wa[8]
    DIRECTION OUTPUT ;
    USE SIGNAL ;
    PORT
      LAYER M4 ;
        RECT  0 12.288 0.084 12.312 ;
    END
  END rf_wa[8]
  PIN rf_wa[9]
    DIRECTION OUTPUT ;
    USE SIGNAL ;
    PORT
      LAYER M4 ;
        RECT  0 12.48 0.084 12.504 ;
    END
  END rf_wa[9]
  PIN rf_wd[0]
    DIRECTION OUTPUT ;
    USE SIGNAL ;
    PORT
      LAYER M4 ;
        RECT  0 16.848 0.084 16.872 ;
    END
  END rf_wd[0]
  PIN rf_wd[100]
    DIRECTION OUTPUT ;
    USE SIGNAL ;
    PORT
      LAYER M4 ;
        RECT  0 35.808 0.084 35.832 ;
    END
  END rf_wd[100]
  PIN rf_wd[101]
    DIRECTION OUTPUT ;
    USE SIGNAL ;
    PORT
      LAYER M4 ;
        RECT  0 36 0.084 36.024 ;
    END
  END rf_wd[101]
  PIN rf_wd[102]
    DIRECTION OUTPUT ;
    USE SIGNAL ;
    PORT
      LAYER M4 ;
        RECT  0 36.192 0.084 36.216 ;
    END
  END rf_wd[102]
  PIN rf_wd[103]
    DIRECTION OUTPUT ;
    USE SIGNAL ;
    PORT
      LAYER M4 ;
        RECT  0 36.384 0.084 36.408 ;
    END
  END rf_wd[103]
  PIN rf_wd[104]
    DIRECTION OUTPUT ;
    USE SIGNAL ;
    PORT
      LAYER M4 ;
        RECT  0 36.576 0.084 36.6 ;
    END
  END rf_wd[104]
  PIN rf_wd[105]
    DIRECTION OUTPUT ;
    USE SIGNAL ;
    PORT
      LAYER M4 ;
        RECT  0 36.768 0.084 36.792 ;
    END
  END rf_wd[105]
  PIN rf_wd[106]
    DIRECTION OUTPUT ;
    USE SIGNAL ;
    PORT
      LAYER M4 ;
        RECT  0 36.96 0.084 36.984 ;
    END
  END rf_wd[106]
  PIN rf_wd[107]
    DIRECTION OUTPUT ;
    USE SIGNAL ;
    PORT
      LAYER M4 ;
        RECT  0 37.152 0.084 37.176 ;
    END
  END rf_wd[107]
  PIN rf_wd[108]
    DIRECTION OUTPUT ;
    USE SIGNAL ;
    PORT
      LAYER M4 ;
        RECT  0 37.344 0.084 37.368 ;
    END
  END rf_wd[108]
  PIN rf_wd[109]
    DIRECTION OUTPUT ;
    USE SIGNAL ;
    PORT
      LAYER M4 ;
        RECT  0 37.536 0.084 37.56 ;
    END
  END rf_wd[109]
  PIN rf_wd[10]
    DIRECTION OUTPUT ;
    USE SIGNAL ;
    PORT
      LAYER M4 ;
        RECT  0 18.72 0.084 18.744 ;
    END
  END rf_wd[10]
  PIN rf_wd[110]
    DIRECTION OUTPUT ;
    USE SIGNAL ;
    PORT
      LAYER M4 ;
        RECT  0 37.728 0.084 37.752 ;
    END
  END rf_wd[110]
  PIN rf_wd[111]
    DIRECTION OUTPUT ;
    USE SIGNAL ;
    PORT
      LAYER M4 ;
        RECT  0 37.92 0.084 37.944 ;
    END
  END rf_wd[111]
  PIN rf_wd[112]
    DIRECTION OUTPUT ;
    USE SIGNAL ;
    PORT
      LAYER M4 ;
        RECT  0 38.112 0.084 38.136 ;
    END
  END rf_wd[112]
  PIN rf_wd[113]
    DIRECTION OUTPUT ;
    USE SIGNAL ;
    PORT
      LAYER M4 ;
        RECT  0 38.256 0.084 38.28 ;
    END
  END rf_wd[113]
  PIN rf_wd[114]
    DIRECTION OUTPUT ;
    USE SIGNAL ;
    PORT
      LAYER M4 ;
        RECT  0 38.448 0.084 38.472 ;
    END
  END rf_wd[114]
  PIN rf_wd[115]
    DIRECTION OUTPUT ;
    USE SIGNAL ;
    PORT
      LAYER M4 ;
        RECT  0 38.64 0.084 38.664 ;
    END
  END rf_wd[115]
  PIN rf_wd[116]
    DIRECTION OUTPUT ;
    USE SIGNAL ;
    PORT
      LAYER M4 ;
        RECT  0 38.832 0.084 38.856 ;
    END
  END rf_wd[116]
  PIN rf_wd[117]
    DIRECTION OUTPUT ;
    USE SIGNAL ;
    PORT
      LAYER M4 ;
        RECT  0 39.024 0.084 39.048 ;
    END
  END rf_wd[117]
  PIN rf_wd[118]
    DIRECTION OUTPUT ;
    USE SIGNAL ;
    PORT
      LAYER M4 ;
        RECT  0 39.216 0.084 39.24 ;
    END
  END rf_wd[118]
  PIN rf_wd[119]
    DIRECTION OUTPUT ;
    USE SIGNAL ;
    PORT
      LAYER M4 ;
        RECT  0 39.408 0.084 39.432 ;
    END
  END rf_wd[119]
  PIN rf_wd[11]
    DIRECTION OUTPUT ;
    USE SIGNAL ;
    PORT
      LAYER M4 ;
        RECT  0 18.912 0.084 18.936 ;
    END
  END rf_wd[11]
  PIN rf_wd[120]
    DIRECTION OUTPUT ;
    USE SIGNAL ;
    PORT
      LAYER M4 ;
        RECT  0 39.6 0.084 39.624 ;
    END
  END rf_wd[120]
  PIN rf_wd[121]
    DIRECTION OUTPUT ;
    USE SIGNAL ;
    PORT
      LAYER M4 ;
        RECT  0 39.792 0.084 39.816 ;
    END
  END rf_wd[121]
  PIN rf_wd[122]
    DIRECTION OUTPUT ;
    USE SIGNAL ;
    PORT
      LAYER M4 ;
        RECT  0 39.984 0.084 40.008 ;
    END
  END rf_wd[122]
  PIN rf_wd[123]
    DIRECTION OUTPUT ;
    USE SIGNAL ;
    PORT
      LAYER M4 ;
        RECT  0 40.176 0.084 40.2 ;
    END
  END rf_wd[123]
  PIN rf_wd[124]
    DIRECTION OUTPUT ;
    USE SIGNAL ;
    PORT
      LAYER M4 ;
        RECT  0 40.368 0.084 40.392 ;
    END
  END rf_wd[124]
  PIN rf_wd[125]
    DIRECTION OUTPUT ;
    USE SIGNAL ;
    PORT
      LAYER M4 ;
        RECT  0 40.56 0.084 40.584 ;
    END
  END rf_wd[125]
  PIN rf_wd[126]
    DIRECTION OUTPUT ;
    USE SIGNAL ;
    PORT
      LAYER M4 ;
        RECT  0 40.752 0.084 40.776 ;
    END
  END rf_wd[126]
  PIN rf_wd[127]
    DIRECTION OUTPUT ;
    USE SIGNAL ;
    PORT
      LAYER M4 ;
        RECT  0 40.944 0.084 40.968 ;
    END
  END rf_wd[127]
  PIN rf_wd[12]
    DIRECTION OUTPUT ;
    USE SIGNAL ;
    PORT
      LAYER M4 ;
        RECT  0 19.104 0.084 19.128 ;
    END
  END rf_wd[12]
  PIN rf_wd[13]
    DIRECTION OUTPUT ;
    USE SIGNAL ;
    PORT
      LAYER M4 ;
        RECT  0 19.296 0.084 19.32 ;
    END
  END rf_wd[13]
  PIN rf_wd[14]
    DIRECTION OUTPUT ;
    USE SIGNAL ;
    PORT
      LAYER M4 ;
        RECT  0 19.488 0.084 19.512 ;
    END
  END rf_wd[14]
  PIN rf_wd[15]
    DIRECTION OUTPUT ;
    USE SIGNAL ;
    PORT
      LAYER M4 ;
        RECT  0 19.68 0.084 19.704 ;
    END
  END rf_wd[15]
  PIN rf_wd[16]
    DIRECTION OUTPUT ;
    USE SIGNAL ;
    PORT
      LAYER M4 ;
        RECT  0 19.872 0.084 19.896 ;
    END
  END rf_wd[16]
  PIN rf_wd[17]
    DIRECTION OUTPUT ;
    USE SIGNAL ;
    PORT
      LAYER M4 ;
        RECT  0 20.064 0.084 20.088 ;
    END
  END rf_wd[17]
  PIN rf_wd[18]
    DIRECTION OUTPUT ;
    USE SIGNAL ;
    PORT
      LAYER M4 ;
        RECT  0 20.256 0.084 20.28 ;
    END
  END rf_wd[18]
  PIN rf_wd[19]
    DIRECTION OUTPUT ;
    USE SIGNAL ;
    PORT
      LAYER M4 ;
        RECT  0 20.448 0.084 20.472 ;
    END
  END rf_wd[19]
  PIN rf_wd[1]
    DIRECTION OUTPUT ;
    USE SIGNAL ;
    PORT
      LAYER M4 ;
        RECT  0 17.04 0.084 17.064 ;
    END
  END rf_wd[1]
  PIN rf_wd[20]
    DIRECTION OUTPUT ;
    USE SIGNAL ;
    PORT
      LAYER M4 ;
        RECT  0 20.64 0.084 20.664 ;
    END
  END rf_wd[20]
  PIN rf_wd[21]
    DIRECTION OUTPUT ;
    USE SIGNAL ;
    PORT
      LAYER M4 ;
        RECT  0 20.832 0.084 20.856 ;
    END
  END rf_wd[21]
  PIN rf_wd[22]
    DIRECTION OUTPUT ;
    USE SIGNAL ;
    PORT
      LAYER M4 ;
        RECT  0 21.024 0.084 21.048 ;
    END
  END rf_wd[22]
  PIN rf_wd[23]
    DIRECTION OUTPUT ;
    USE SIGNAL ;
    PORT
      LAYER M4 ;
        RECT  0 21.216 0.084 21.24 ;
    END
  END rf_wd[23]
  PIN rf_wd[24]
    DIRECTION OUTPUT ;
    USE SIGNAL ;
    PORT
      LAYER M4 ;
        RECT  0 21.408 0.084 21.432 ;
    END
  END rf_wd[24]
  PIN rf_wd[25]
    DIRECTION OUTPUT ;
    USE SIGNAL ;
    PORT
      LAYER M4 ;
        RECT  0 21.6 0.084 21.624 ;
    END
  END rf_wd[25]
  PIN rf_wd[26]
    DIRECTION OUTPUT ;
    USE SIGNAL ;
    PORT
      LAYER M4 ;
        RECT  0 21.792 0.084 21.816 ;
    END
  END rf_wd[26]
  PIN rf_wd[27]
    DIRECTION OUTPUT ;
    USE SIGNAL ;
    PORT
      LAYER M4 ;
        RECT  0 21.984 0.084 22.008 ;
    END
  END rf_wd[27]
  PIN rf_wd[28]
    DIRECTION OUTPUT ;
    USE SIGNAL ;
    PORT
      LAYER M4 ;
        RECT  0 22.176 0.084 22.2 ;
    END
  END rf_wd[28]
  PIN rf_wd[29]
    DIRECTION OUTPUT ;
    USE SIGNAL ;
    PORT
      LAYER M4 ;
        RECT  0 22.368 0.084 22.392 ;
    END
  END rf_wd[29]
  PIN rf_wd[2]
    DIRECTION OUTPUT ;
    USE SIGNAL ;
    PORT
      LAYER M4 ;
        RECT  0 17.232 0.084 17.256 ;
    END
  END rf_wd[2]
  PIN rf_wd[30]
    DIRECTION OUTPUT ;
    USE SIGNAL ;
    PORT
      LAYER M4 ;
        RECT  0 22.56 0.084 22.584 ;
    END
  END rf_wd[30]
  PIN rf_wd[31]
    DIRECTION OUTPUT ;
    USE SIGNAL ;
    PORT
      LAYER M4 ;
        RECT  0 22.704 0.084 22.728 ;
    END
  END rf_wd[31]
  PIN rf_wd[32]
    DIRECTION OUTPUT ;
    USE SIGNAL ;
    PORT
      LAYER M4 ;
        RECT  0 22.896 0.084 22.92 ;
    END
  END rf_wd[32]
  PIN rf_wd[33]
    DIRECTION OUTPUT ;
    USE SIGNAL ;
    PORT
      LAYER M4 ;
        RECT  0 23.088 0.084 23.112 ;
    END
  END rf_wd[33]
  PIN rf_wd[34]
    DIRECTION OUTPUT ;
    USE SIGNAL ;
    PORT
      LAYER M4 ;
        RECT  0 23.28 0.084 23.304 ;
    END
  END rf_wd[34]
  PIN rf_wd[35]
    DIRECTION OUTPUT ;
    USE SIGNAL ;
    PORT
      LAYER M4 ;
        RECT  0 23.472 0.084 23.496 ;
    END
  END rf_wd[35]
  PIN rf_wd[36]
    DIRECTION OUTPUT ;
    USE SIGNAL ;
    PORT
      LAYER M4 ;
        RECT  0 23.664 0.084 23.688 ;
    END
  END rf_wd[36]
  PIN rf_wd[37]
    DIRECTION OUTPUT ;
    USE SIGNAL ;
    PORT
      LAYER M4 ;
        RECT  0 23.856 0.084 23.88 ;
    END
  END rf_wd[37]
  PIN rf_wd[38]
    DIRECTION OUTPUT ;
    USE SIGNAL ;
    PORT
      LAYER M4 ;
        RECT  0 24.048 0.084 24.072 ;
    END
  END rf_wd[38]
  PIN rf_wd[39]
    DIRECTION OUTPUT ;
    USE SIGNAL ;
    PORT
      LAYER M4 ;
        RECT  0 24.24 0.084 24.264 ;
    END
  END rf_wd[39]
  PIN rf_wd[3]
    DIRECTION OUTPUT ;
    USE SIGNAL ;
    PORT
      LAYER M4 ;
        RECT  0 17.424 0.084 17.448 ;
    END
  END rf_wd[3]
  PIN rf_wd[40]
    DIRECTION OUTPUT ;
    USE SIGNAL ;
    PORT
      LAYER M4 ;
        RECT  0 24.432 0.084 24.456 ;
    END
  END rf_wd[40]
  PIN rf_wd[41]
    DIRECTION OUTPUT ;
    USE SIGNAL ;
    PORT
      LAYER M4 ;
        RECT  0 24.624 0.084 24.648 ;
    END
  END rf_wd[41]
  PIN rf_wd[42]
    DIRECTION OUTPUT ;
    USE SIGNAL ;
    PORT
      LAYER M4 ;
        RECT  0 24.816 0.084 24.84 ;
    END
  END rf_wd[42]
  PIN rf_wd[43]
    DIRECTION OUTPUT ;
    USE SIGNAL ;
    PORT
      LAYER M4 ;
        RECT  0 25.008 0.084 25.032 ;
    END
  END rf_wd[43]
  PIN rf_wd[44]
    DIRECTION OUTPUT ;
    USE SIGNAL ;
    PORT
      LAYER M4 ;
        RECT  0 25.2 0.084 25.224 ;
    END
  END rf_wd[44]
  PIN rf_wd[45]
    DIRECTION OUTPUT ;
    USE SIGNAL ;
    PORT
      LAYER M4 ;
        RECT  0 25.392 0.084 25.416 ;
    END
  END rf_wd[45]
  PIN rf_wd[46]
    DIRECTION OUTPUT ;
    USE SIGNAL ;
    PORT
      LAYER M4 ;
        RECT  0 25.584 0.084 25.608 ;
    END
  END rf_wd[46]
  PIN rf_wd[47]
    DIRECTION OUTPUT ;
    USE SIGNAL ;
    PORT
      LAYER M4 ;
        RECT  0 25.776 0.084 25.8 ;
    END
  END rf_wd[47]
  PIN rf_wd[48]
    DIRECTION OUTPUT ;
    USE SIGNAL ;
    PORT
      LAYER M4 ;
        RECT  0 25.968 0.084 25.992 ;
    END
  END rf_wd[48]
  PIN rf_wd[49]
    DIRECTION OUTPUT ;
    USE SIGNAL ;
    PORT
      LAYER M4 ;
        RECT  0 26.16 0.084 26.184 ;
    END
  END rf_wd[49]
  PIN rf_wd[4]
    DIRECTION OUTPUT ;
    USE SIGNAL ;
    PORT
      LAYER M4 ;
        RECT  0 17.616 0.084 17.64 ;
    END
  END rf_wd[4]
  PIN rf_wd[50]
    DIRECTION OUTPUT ;
    USE SIGNAL ;
    PORT
      LAYER M4 ;
        RECT  0 26.352 0.084 26.376 ;
    END
  END rf_wd[50]
  PIN rf_wd[51]
    DIRECTION OUTPUT ;
    USE SIGNAL ;
    PORT
      LAYER M4 ;
        RECT  0 26.496 0.084 26.52 ;
    END
  END rf_wd[51]
  PIN rf_wd[52]
    DIRECTION OUTPUT ;
    USE SIGNAL ;
    PORT
      LAYER M4 ;
        RECT  0 26.688 0.084 26.712 ;
    END
  END rf_wd[52]
  PIN rf_wd[53]
    DIRECTION OUTPUT ;
    USE SIGNAL ;
    PORT
      LAYER M4 ;
        RECT  0 26.88 0.084 26.904 ;
    END
  END rf_wd[53]
  PIN rf_wd[54]
    DIRECTION OUTPUT ;
    USE SIGNAL ;
    PORT
      LAYER M4 ;
        RECT  0 27.072 0.084 27.096 ;
    END
  END rf_wd[54]
  PIN rf_wd[55]
    DIRECTION OUTPUT ;
    USE SIGNAL ;
    PORT
      LAYER M4 ;
        RECT  0 27.264 0.084 27.288 ;
    END
  END rf_wd[55]
  PIN rf_wd[56]
    DIRECTION OUTPUT ;
    USE SIGNAL ;
    PORT
      LAYER M4 ;
        RECT  0 27.456 0.084 27.48 ;
    END
  END rf_wd[56]
  PIN rf_wd[57]
    DIRECTION OUTPUT ;
    USE SIGNAL ;
    PORT
      LAYER M4 ;
        RECT  0 27.648 0.084 27.672 ;
    END
  END rf_wd[57]
  PIN rf_wd[58]
    DIRECTION OUTPUT ;
    USE SIGNAL ;
    PORT
      LAYER M4 ;
        RECT  0 27.84 0.084 27.864 ;
    END
  END rf_wd[58]
  PIN rf_wd[59]
    DIRECTION OUTPUT ;
    USE SIGNAL ;
    PORT
      LAYER M4 ;
        RECT  0 28.032 0.084 28.056 ;
    END
  END rf_wd[59]
  PIN rf_wd[5]
    DIRECTION OUTPUT ;
    USE SIGNAL ;
    PORT
      LAYER M4 ;
        RECT  0 17.808 0.084 17.832 ;
    END
  END rf_wd[5]
  PIN rf_wd[60]
    DIRECTION OUTPUT ;
    USE SIGNAL ;
    PORT
      LAYER M4 ;
        RECT  0 28.224 0.084 28.248 ;
    END
  END rf_wd[60]
  PIN rf_wd[61]
    DIRECTION OUTPUT ;
    USE SIGNAL ;
    PORT
      LAYER M4 ;
        RECT  0 28.416 0.084 28.44 ;
    END
  END rf_wd[61]
  PIN rf_wd[62]
    DIRECTION OUTPUT ;
    USE SIGNAL ;
    PORT
      LAYER M4 ;
        RECT  0 28.608 0.084 28.632 ;
    END
  END rf_wd[62]
  PIN rf_wd[63]
    DIRECTION OUTPUT ;
    USE SIGNAL ;
    PORT
      LAYER M4 ;
        RECT  0 28.8 0.084 28.824 ;
    END
  END rf_wd[63]
  PIN rf_wd[64]
    DIRECTION OUTPUT ;
    USE SIGNAL ;
    PORT
      LAYER M4 ;
        RECT  0 28.992 0.084 29.016 ;
    END
  END rf_wd[64]
  PIN rf_wd[65]
    DIRECTION OUTPUT ;
    USE SIGNAL ;
    PORT
      LAYER M4 ;
        RECT  0 29.184 0.084 29.208 ;
    END
  END rf_wd[65]
  PIN rf_wd[66]
    DIRECTION OUTPUT ;
    USE SIGNAL ;
    PORT
      LAYER M4 ;
        RECT  0 29.376 0.084 29.4 ;
    END
  END rf_wd[66]
  PIN rf_wd[67]
    DIRECTION OUTPUT ;
    USE SIGNAL ;
    PORT
      LAYER M4 ;
        RECT  0 29.568 0.084 29.592 ;
    END
  END rf_wd[67]
  PIN rf_wd[68]
    DIRECTION OUTPUT ;
    USE SIGNAL ;
    PORT
      LAYER M4 ;
        RECT  0 29.76 0.084 29.784 ;
    END
  END rf_wd[68]
  PIN rf_wd[69]
    DIRECTION OUTPUT ;
    USE SIGNAL ;
    PORT
      LAYER M4 ;
        RECT  0 29.952 0.084 29.976 ;
    END
  END rf_wd[69]
  PIN rf_wd[6]
    DIRECTION OUTPUT ;
    USE SIGNAL ;
    PORT
      LAYER M4 ;
        RECT  0 18 0.084 18.024 ;
    END
  END rf_wd[6]
  PIN rf_wd[70]
    DIRECTION OUTPUT ;
    USE SIGNAL ;
    PORT
      LAYER M4 ;
        RECT  0 30.144 0.084 30.168 ;
    END
  END rf_wd[70]
  PIN rf_wd[71]
    DIRECTION OUTPUT ;
    USE SIGNAL ;
    PORT
      LAYER M4 ;
        RECT  0 30.336 0.084 30.36 ;
    END
  END rf_wd[71]
  PIN rf_wd[72]
    DIRECTION OUTPUT ;
    USE SIGNAL ;
    PORT
      LAYER M4 ;
        RECT  0 30.48 0.084 30.504 ;
    END
  END rf_wd[72]
  PIN rf_wd[73]
    DIRECTION OUTPUT ;
    USE SIGNAL ;
    PORT
      LAYER M4 ;
        RECT  0 30.672 0.084 30.696 ;
    END
  END rf_wd[73]
  PIN rf_wd[74]
    DIRECTION OUTPUT ;
    USE SIGNAL ;
    PORT
      LAYER M4 ;
        RECT  0 30.864 0.084 30.888 ;
    END
  END rf_wd[74]
  PIN rf_wd[75]
    DIRECTION OUTPUT ;
    USE SIGNAL ;
    PORT
      LAYER M4 ;
        RECT  0 31.056 0.084 31.08 ;
    END
  END rf_wd[75]
  PIN rf_wd[76]
    DIRECTION OUTPUT ;
    USE SIGNAL ;
    PORT
      LAYER M4 ;
        RECT  0 31.248 0.084 31.272 ;
    END
  END rf_wd[76]
  PIN rf_wd[77]
    DIRECTION OUTPUT ;
    USE SIGNAL ;
    PORT
      LAYER M4 ;
        RECT  0 31.44 0.084 31.464 ;
    END
  END rf_wd[77]
  PIN rf_wd[78]
    DIRECTION OUTPUT ;
    USE SIGNAL ;
    PORT
      LAYER M4 ;
        RECT  0 31.632 0.084 31.656 ;
    END
  END rf_wd[78]
  PIN rf_wd[79]
    DIRECTION OUTPUT ;
    USE SIGNAL ;
    PORT
      LAYER M4 ;
        RECT  0 31.824 0.084 31.848 ;
    END
  END rf_wd[79]
  PIN rf_wd[7]
    DIRECTION OUTPUT ;
    USE SIGNAL ;
    PORT
      LAYER M4 ;
        RECT  0 18.192 0.084 18.216 ;
    END
  END rf_wd[7]
  PIN rf_wd[80]
    DIRECTION OUTPUT ;
    USE SIGNAL ;
    PORT
      LAYER M4 ;
        RECT  0 32.016 0.084 32.04 ;
    END
  END rf_wd[80]
  PIN rf_wd[81]
    DIRECTION OUTPUT ;
    USE SIGNAL ;
    PORT
      LAYER M4 ;
        RECT  0 32.208 0.084 32.232 ;
    END
  END rf_wd[81]
  PIN rf_wd[82]
    DIRECTION OUTPUT ;
    USE SIGNAL ;
    PORT
      LAYER M4 ;
        RECT  0 32.4 0.084 32.424 ;
    END
  END rf_wd[82]
  PIN rf_wd[83]
    DIRECTION OUTPUT ;
    USE SIGNAL ;
    PORT
      LAYER M4 ;
        RECT  0 32.592 0.084 32.616 ;
    END
  END rf_wd[83]
  PIN rf_wd[84]
    DIRECTION OUTPUT ;
    USE SIGNAL ;
    PORT
      LAYER M4 ;
        RECT  0 32.784 0.084 32.808 ;
    END
  END rf_wd[84]
  PIN rf_wd[85]
    DIRECTION OUTPUT ;
    USE SIGNAL ;
    PORT
      LAYER M4 ;
        RECT  0 32.976 0.084 33 ;
    END
  END rf_wd[85]
  PIN rf_wd[86]
    DIRECTION OUTPUT ;
    USE SIGNAL ;
    PORT
      LAYER M4 ;
        RECT  0 33.168 0.084 33.192 ;
    END
  END rf_wd[86]
  PIN rf_wd[87]
    DIRECTION OUTPUT ;
    USE SIGNAL ;
    PORT
      LAYER M4 ;
        RECT  0 33.36 0.084 33.384 ;
    END
  END rf_wd[87]
  PIN rf_wd[88]
    DIRECTION OUTPUT ;
    USE SIGNAL ;
    PORT
      LAYER M4 ;
        RECT  0 33.552 0.084 33.576 ;
    END
  END rf_wd[88]
  PIN rf_wd[89]
    DIRECTION OUTPUT ;
    USE SIGNAL ;
    PORT
      LAYER M4 ;
        RECT  0 33.744 0.084 33.768 ;
    END
  END rf_wd[89]
  PIN rf_wd[8]
    DIRECTION OUTPUT ;
    USE SIGNAL ;
    PORT
      LAYER M4 ;
        RECT  0 18.384 0.084 18.408 ;
    END
  END rf_wd[8]
  PIN rf_wd[90]
    DIRECTION OUTPUT ;
    USE SIGNAL ;
    PORT
      LAYER M4 ;
        RECT  0 33.936 0.084 33.96 ;
    END
  END rf_wd[90]
  PIN rf_wd[91]
    DIRECTION OUTPUT ;
    USE SIGNAL ;
    PORT
      LAYER M4 ;
        RECT  0 34.128 0.084 34.152 ;
    END
  END rf_wd[91]
  PIN rf_wd[92]
    DIRECTION OUTPUT ;
    USE SIGNAL ;
    PORT
      LAYER M4 ;
        RECT  0 34.272 0.084 34.296 ;
    END
  END rf_wd[92]
  PIN rf_wd[93]
    DIRECTION OUTPUT ;
    USE SIGNAL ;
    PORT
      LAYER M4 ;
        RECT  0 34.464 0.084 34.488 ;
    END
  END rf_wd[93]
  PIN rf_wd[94]
    DIRECTION OUTPUT ;
    USE SIGNAL ;
    PORT
      LAYER M4 ;
        RECT  0 34.656 0.084 34.68 ;
    END
  END rf_wd[94]
  PIN rf_wd[95]
    DIRECTION OUTPUT ;
    USE SIGNAL ;
    PORT
      LAYER M4 ;
        RECT  0 34.848 0.084 34.872 ;
    END
  END rf_wd[95]
  PIN rf_wd[96]
    DIRECTION OUTPUT ;
    USE SIGNAL ;
    PORT
      LAYER M4 ;
        RECT  0 35.04 0.084 35.064 ;
    END
  END rf_wd[96]
  PIN rf_wd[97]
    DIRECTION OUTPUT ;
    USE SIGNAL ;
    PORT
      LAYER M4 ;
        RECT  0 35.232 0.084 35.256 ;
    END
  END rf_wd[97]
  PIN rf_wd[98]
    DIRECTION OUTPUT ;
    USE SIGNAL ;
    PORT
      LAYER M4 ;
        RECT  0 35.424 0.084 35.448 ;
    END
  END rf_wd[98]
  PIN rf_wd[99]
    DIRECTION OUTPUT ;
    USE SIGNAL ;
    PORT
      LAYER M4 ;
        RECT  0 35.616 0.084 35.64 ;
    END
  END rf_wd[99]
  PIN rf_wd[9]
    DIRECTION OUTPUT ;
    USE SIGNAL ;
    PORT
      LAYER M4 ;
        RECT  0 18.576 0.084 18.6 ;
    END
  END rf_wd[9]
  PIN rf_wv[0]
    DIRECTION OUTPUT ;
    USE SIGNAL ;
    PORT
      LAYER M4 ;
        RECT  0 10.032 0.084 10.056 ;
    END
  END rf_wv[0]
  PIN rf_wv[1]
    DIRECTION OUTPUT ;
    USE SIGNAL ;
    PORT
      LAYER M4 ;
        RECT  0 10.224 0.084 10.248 ;
    END
  END rf_wv[1]
  PIN rf_wv[2]
    DIRECTION OUTPUT ;
    USE SIGNAL ;
    PORT
      LAYER M4 ;
        RECT  0 10.416 0.084 10.44 ;
    END
  END rf_wv[2]
  PIN rf_wv[3]
    DIRECTION OUTPUT ;
    USE SIGNAL ;
    PORT
      LAYER M4 ;
        RECT  0 10.608 0.084 10.632 ;
    END
  END rf_wv[3]
  PIN rst_n
    DIRECTION INPUT ;
    USE SIGNAL ;
    PORT
      LAYER M3 ;
        RECT  22.68 43.162 22.698 43.2 ;
    END
  END rst_n
  PIN up_o[0]
    DIRECTION OUTPUT ;
    USE SIGNAL ;
    PORT
      LAYER M4 ;
        RECT  43.116 2.256 43.2 2.28 ;
    END
  END up_o[0]
  PIN up_o[10]
    DIRECTION OUTPUT ;
    USE SIGNAL ;
    PORT
      LAYER M4 ;
        RECT  43.116 4.128 43.2 4.152 ;
    END
  END up_o[10]
  PIN up_o[11]
    DIRECTION OUTPUT ;
    USE SIGNAL ;
    PORT
      LAYER M4 ;
        RECT  43.116 4.32 43.2 4.344 ;
    END
  END up_o[11]
  PIN up_o[12]
    DIRECTION OUTPUT ;
    USE SIGNAL ;
    PORT
      LAYER M4 ;
        RECT  43.116 4.512 43.2 4.536 ;
    END
  END up_o[12]
  PIN up_o[13]
    DIRECTION OUTPUT ;
    USE SIGNAL ;
    PORT
      LAYER M4 ;
        RECT  43.116 4.704 43.2 4.728 ;
    END
  END up_o[13]
  PIN up_o[14]
    DIRECTION OUTPUT ;
    USE SIGNAL ;
    PORT
      LAYER M4 ;
        RECT  43.116 4.896 43.2 4.92 ;
    END
  END up_o[14]
  PIN up_o[15]
    DIRECTION OUTPUT ;
    USE SIGNAL ;
    PORT
      LAYER M4 ;
        RECT  43.116 5.088 43.2 5.112 ;
    END
  END up_o[15]
  PIN up_o[16]
    DIRECTION OUTPUT ;
    USE SIGNAL ;
    PORT
      LAYER M4 ;
        RECT  43.116 5.28 43.2 5.304 ;
    END
  END up_o[16]
  PIN up_o[17]
    DIRECTION OUTPUT ;
    USE SIGNAL ;
    PORT
      LAYER M4 ;
        RECT  43.116 5.472 43.2 5.496 ;
    END
  END up_o[17]
  PIN up_o[18]
    DIRECTION OUTPUT ;
    USE SIGNAL ;
    PORT
      LAYER M4 ;
        RECT  43.116 5.664 43.2 5.688 ;
    END
  END up_o[18]
  PIN up_o[19]
    DIRECTION OUTPUT ;
    USE SIGNAL ;
    PORT
      LAYER M4 ;
        RECT  43.116 5.856 43.2 5.88 ;
    END
  END up_o[19]
  PIN up_o[1]
    DIRECTION OUTPUT ;
    USE SIGNAL ;
    PORT
      LAYER M4 ;
        RECT  43.116 2.448 43.2 2.472 ;
    END
  END up_o[1]
  PIN up_o[20]
    DIRECTION OUTPUT ;
    USE SIGNAL ;
    PORT
      LAYER M4 ;
        RECT  43.116 6.048 43.2 6.072 ;
    END
  END up_o[20]
  PIN up_o[21]
    DIRECTION OUTPUT ;
    USE SIGNAL ;
    PORT
      LAYER M4 ;
        RECT  43.116 6.24 43.2 6.264 ;
    END
  END up_o[21]
  PIN up_o[22]
    DIRECTION OUTPUT ;
    USE SIGNAL ;
    PORT
      LAYER M4 ;
        RECT  43.116 6.432 43.2 6.456 ;
    END
  END up_o[22]
  PIN up_o[23]
    DIRECTION OUTPUT ;
    USE SIGNAL ;
    PORT
      LAYER M4 ;
        RECT  43.116 6.624 43.2 6.648 ;
    END
  END up_o[23]
  PIN up_o[24]
    DIRECTION OUTPUT ;
    USE SIGNAL ;
    PORT
      LAYER M4 ;
        RECT  43.116 6.816 43.2 6.84 ;
    END
  END up_o[24]
  PIN up_o[25]
    DIRECTION OUTPUT ;
    USE SIGNAL ;
    PORT
      LAYER M4 ;
        RECT  43.116 7.008 43.2 7.032 ;
    END
  END up_o[25]
  PIN up_o[26]
    DIRECTION OUTPUT ;
    USE SIGNAL ;
    PORT
      LAYER M4 ;
        RECT  43.116 7.152 43.2 7.176 ;
    END
  END up_o[26]
  PIN up_o[27]
    DIRECTION OUTPUT ;
    USE SIGNAL ;
    PORT
      LAYER M4 ;
        RECT  43.116 7.344 43.2 7.368 ;
    END
  END up_o[27]
  PIN up_o[28]
    DIRECTION OUTPUT ;
    USE SIGNAL ;
    PORT
      LAYER M4 ;
        RECT  43.116 7.536 43.2 7.56 ;
    END
  END up_o[28]
  PIN up_o[29]
    DIRECTION OUTPUT ;
    USE SIGNAL ;
    PORT
      LAYER M4 ;
        RECT  43.116 7.728 43.2 7.752 ;
    END
  END up_o[29]
  PIN up_o[2]
    DIRECTION OUTPUT ;
    USE SIGNAL ;
    PORT
      LAYER M4 ;
        RECT  43.116 2.64 43.2 2.664 ;
    END
  END up_o[2]
  PIN up_o[30]
    DIRECTION OUTPUT ;
    USE SIGNAL ;
    PORT
      LAYER M4 ;
        RECT  43.116 7.92 43.2 7.944 ;
    END
  END up_o[30]
  PIN up_o[31]
    DIRECTION OUTPUT ;
    USE SIGNAL ;
    PORT
      LAYER M4 ;
        RECT  43.116 8.112 43.2 8.136 ;
    END
  END up_o[31]
  PIN up_o[32]
    DIRECTION OUTPUT ;
    USE SIGNAL ;
    PORT
      LAYER M4 ;
        RECT  43.116 8.304 43.2 8.328 ;
    END
  END up_o[32]
  PIN up_o[33]
    DIRECTION OUTPUT ;
    USE SIGNAL ;
    PORT
      LAYER M4 ;
        RECT  43.116 8.496 43.2 8.52 ;
    END
  END up_o[33]
  PIN up_o[34]
    DIRECTION OUTPUT ;
    USE SIGNAL ;
    PORT
      LAYER M4 ;
        RECT  43.116 8.688 43.2 8.712 ;
    END
  END up_o[34]
  PIN up_o[35]
    DIRECTION OUTPUT ;
    USE SIGNAL ;
    PORT
      LAYER M4 ;
        RECT  43.116 8.88 43.2 8.904 ;
    END
  END up_o[35]
  PIN up_o[36]
    DIRECTION OUTPUT ;
    USE SIGNAL ;
    PORT
      LAYER M4 ;
        RECT  43.116 9.072 43.2 9.096 ;
    END
  END up_o[36]
  PIN up_o[37]
    DIRECTION OUTPUT ;
    USE SIGNAL ;
    PORT
      LAYER M4 ;
        RECT  43.116 9.264 43.2 9.288 ;
    END
  END up_o[37]
  PIN up_o[38]
    DIRECTION OUTPUT ;
    USE SIGNAL ;
    PORT
      LAYER M4 ;
        RECT  43.116 9.456 43.2 9.48 ;
    END
  END up_o[38]
  PIN up_o[39]
    DIRECTION OUTPUT ;
    USE SIGNAL ;
    PORT
      LAYER M4 ;
        RECT  43.116 9.648 43.2 9.672 ;
    END
  END up_o[39]
  PIN up_o[3]
    DIRECTION OUTPUT ;
    USE SIGNAL ;
    PORT
      LAYER M4 ;
        RECT  43.116 2.832 43.2 2.856 ;
    END
  END up_o[3]
  PIN up_o[40]
    DIRECTION OUTPUT ;
    USE SIGNAL ;
    PORT
      LAYER M4 ;
        RECT  43.116 9.84 43.2 9.864 ;
    END
  END up_o[40]
  PIN up_o[4]
    DIRECTION OUTPUT ;
    USE SIGNAL ;
    PORT
      LAYER M4 ;
        RECT  43.116 3.024 43.2 3.048 ;
    END
  END up_o[4]
  PIN up_o[5]
    DIRECTION OUTPUT ;
    USE SIGNAL ;
    PORT
      LAYER M4 ;
        RECT  43.116 3.168 43.2 3.192 ;
    END
  END up_o[5]
  PIN up_o[6]
    DIRECTION OUTPUT ;
    USE SIGNAL ;
    PORT
      LAYER M4 ;
        RECT  43.116 3.36 43.2 3.384 ;
    END
  END up_o[6]
  PIN up_o[7]
    DIRECTION OUTPUT ;
    USE SIGNAL ;
    PORT
      LAYER M4 ;
        RECT  43.116 3.552 43.2 3.576 ;
    END
  END up_o[7]
  PIN up_o[8]
    DIRECTION OUTPUT ;
    USE SIGNAL ;
    PORT
      LAYER M4 ;
        RECT  43.116 3.744 43.2 3.768 ;
    END
  END up_o[8]
  PIN up_o[9]
    DIRECTION OUTPUT ;
    USE SIGNAL ;
    PORT
      LAYER M4 ;
        RECT  43.116 3.936 43.2 3.96 ;
    END
  END up_o[9]
  PIN VDD
    DIRECTION INOUT ;
    USE POWER ;
    PORT
      LAYER M5 ;
        RECT  40.392 2.151 40.512 41.049 ;
        RECT  34.992 2.151 35.112 41.049 ;
        RECT  29.592 2.151 29.712 41.049 ;
        RECT  24.192 2.151 24.312 41.049 ;
        RECT  18.792 2.151 18.912 41.049 ;
        RECT  13.392 2.151 13.512 41.049 ;
        RECT  7.992 2.151 8.112 41.049 ;
        RECT  2.592 2.151 2.712 41.049 ;
    END
  END VDD
  PIN VSS
    DIRECTION INOUT ;
    USE GROUND ;
    PORT
      LAYER M5 ;
        RECT  40.2 2.137 40.32 41.063 ;
        RECT  34.8 2.137 34.92 41.063 ;
        RECT  29.4 2.137 29.52 41.063 ;
        RECT  24 2.137 24.12 41.063 ;
        RECT  18.6 2.137 18.72 41.063 ;
        RECT  13.2 2.137 13.32 41.063 ;
        RECT  7.8 2.137 7.92 41.063 ;
        RECT  2.4 2.137 2.52 41.063 ;
    END
  END VSS
  OBS
    LAYER RVTN ;
     RECT  2.16 2.16 41.04 2.295 ;
     RECT  2.16 2.565 41.04 2.835 ;
     RECT  2.16 3.105 41.04 3.375 ;
     RECT  2.16 3.645 41.04 3.915 ;
     RECT  2.16 4.185 41.04 4.455 ;
     RECT  2.16 4.725 41.04 4.995 ;
     RECT  2.16 5.265 41.04 5.535 ;
     RECT  2.16 5.805 41.04 6.075 ;
     RECT  2.16 6.345 41.04 6.615 ;
     RECT  2.16 6.885 41.04 7.155 ;
     RECT  2.16 7.425 41.04 7.695 ;
     RECT  2.16 7.965 41.04 8.235 ;
     RECT  2.16 8.505 41.04 8.775 ;
     RECT  2.16 9.045 41.04 9.315 ;
     RECT  2.16 9.585 41.04 9.855 ;
     RECT  2.16 10.125 41.04 10.395 ;
     RECT  2.16 10.665 41.04 10.935 ;
     RECT  2.16 11.205 41.04 11.475 ;
     RECT  2.16 11.745 41.04 12.015 ;
     RECT  2.16 12.285 41.04 12.555 ;
     RECT  2.16 12.825 41.04 13.095 ;
     RECT  2.16 13.365 41.04 13.635 ;
     RECT  2.16 13.905 41.04 14.175 ;
     RECT  2.16 14.445 41.04 14.715 ;
     RECT  2.16 14.985 41.04 15.255 ;
     RECT  2.16 15.525 41.04 15.795 ;
     RECT  2.16 16.065 41.04 16.335 ;
     RECT  2.16 16.605 41.04 16.875 ;
     RECT  2.16 17.145 41.04 17.415 ;
     RECT  2.16 17.685 41.04 17.955 ;
     RECT  2.16 18.225 41.04 18.495 ;
     RECT  2.16 18.765 41.04 19.035 ;
     RECT  2.16 19.305 41.04 19.575 ;
     RECT  2.16 19.845 41.04 20.115 ;
     RECT  2.16 20.385 41.04 20.655 ;
     RECT  2.16 20.925 41.04 21.195 ;
     RECT  2.16 21.465 41.04 21.735 ;
     RECT  2.16 22.005 41.04 22.275 ;
     RECT  2.16 22.545 41.04 22.815 ;
     RECT  2.16 23.085 41.04 23.355 ;
     RECT  2.16 23.625 41.04 23.895 ;
     RECT  2.16 24.165 41.04 24.435 ;
     RECT  2.16 24.705 41.04 24.975 ;
     RECT  2.16 25.245 41.04 25.515 ;
     RECT  2.16 25.785 41.04 26.055 ;
     RECT  2.16 26.325 41.04 26.595 ;
     RECT  2.16 26.865 41.04 27.135 ;
     RECT  2.16 27.405 41.04 27.675 ;
     RECT  2.16 27.945 41.04 28.215 ;
     RECT  2.16 28.485 41.04 28.755 ;
     RECT  2.16 29.025 41.04 29.295 ;
     RECT  2.16 29.565 41.04 29.835 ;
     RECT  2.16 30.105 41.04 30.375 ;
     RECT  2.16 30.645 41.04 30.915 ;
     RECT  2.16 31.185 41.04 31.455 ;
     RECT  2.16 31.725 41.04 31.995 ;
     RECT  2.16 32.265 41.04 32.535 ;
     RECT  2.16 32.805 41.04 33.075 ;
     RECT  2.16 33.345 41.04 33.615 ;
     RECT  2.16 33.885 41.04 34.155 ;
     RECT  2.16 34.425 41.04 34.695 ;
     RECT  2.16 34.965 41.04 35.235 ;
     RECT  2.16 35.505 41.04 35.775 ;
     RECT  2.16 36.045 41.04 36.315 ;
     RECT  2.16 36.585 41.04 36.855 ;
     RECT  2.16 37.125 41.04 37.395 ;
     RECT  2.16 37.665 41.04 37.935 ;
     RECT  2.16 38.205 41.04 38.475 ;
     RECT  2.16 38.745 41.04 39.015 ;
     RECT  2.16 39.285 41.04 39.555 ;
     RECT  2.16 39.825 41.04 40.095 ;
     RECT  2.16 40.365 41.04 40.635 ;
     RECT  2.16 40.905 41.04 41.04 ;
    LAYER RVTP ;
     RECT  2.16 2.295 41.04 2.565 ;
     RECT  2.16 2.835 41.04 3.105 ;
     RECT  2.16 3.375 41.04 3.645 ;
     RECT  2.16 3.915 41.04 4.185 ;
     RECT  2.16 4.455 41.04 4.725 ;
     RECT  2.16 4.995 41.04 5.265 ;
     RECT  2.16 5.535 41.04 5.805 ;
     RECT  2.16 6.075 41.04 6.345 ;
     RECT  2.16 6.615 41.04 6.885 ;
     RECT  2.16 7.155 41.04 7.425 ;
     RECT  2.16 7.695 41.04 7.965 ;
     RECT  2.16 8.235 41.04 8.505 ;
     RECT  2.16 8.775 41.04 9.045 ;
     RECT  2.16 9.315 41.04 9.585 ;
     RECT  2.16 9.855 41.04 10.125 ;
     RECT  2.16 10.395 41.04 10.665 ;
     RECT  2.16 10.935 41.04 11.205 ;
     RECT  2.16 11.475 41.04 11.745 ;
     RECT  2.16 12.015 41.04 12.285 ;
     RECT  2.16 12.555 41.04 12.825 ;
     RECT  2.16 13.095 41.04 13.365 ;
     RECT  2.16 13.635 41.04 13.905 ;
     RECT  2.16 14.175 41.04 14.445 ;
     RECT  2.16 14.715 41.04 14.985 ;
     RECT  2.16 15.255 41.04 15.525 ;
     RECT  2.16 15.795 41.04 16.065 ;
     RECT  2.16 16.335 41.04 16.605 ;
     RECT  2.16 16.875 41.04 17.145 ;
     RECT  2.16 17.415 41.04 17.685 ;
     RECT  2.16 17.955 41.04 18.225 ;
     RECT  2.16 18.495 41.04 18.765 ;
     RECT  2.16 19.035 41.04 19.305 ;
     RECT  2.16 19.575 41.04 19.845 ;
     RECT  2.16 20.115 41.04 20.385 ;
     RECT  2.16 20.655 41.04 20.925 ;
     RECT  2.16 21.195 41.04 21.465 ;
     RECT  2.16 21.735 41.04 22.005 ;
     RECT  2.16 22.275 41.04 22.545 ;
     RECT  2.16 22.815 41.04 23.085 ;
     RECT  2.16 23.355 41.04 23.625 ;
     RECT  2.16 23.895 41.04 24.165 ;
     RECT  2.16 24.435 41.04 24.705 ;
     RECT  2.16 24.975 41.04 25.245 ;
     RECT  2.16 25.515 41.04 25.785 ;
     RECT  2.16 26.055 41.04 26.325 ;
     RECT  2.16 26.595 41.04 26.865 ;
     RECT  2.16 27.135 41.04 27.405 ;
     RECT  2.16 27.675 41.04 27.945 ;
     RECT  2.16 28.215 41.04 28.485 ;
     RECT  2.16 28.755 41.04 29.025 ;
     RECT  2.16 29.295 41.04 29.565 ;
     RECT  2.16 29.835 41.04 30.105 ;
     RECT  2.16 30.375 41.04 30.645 ;
     RECT  2.16 30.915 41.04 31.185 ;
     RECT  2.16 31.455 41.04 31.725 ;
     RECT  2.16 31.995 41.04 32.265 ;
     RECT  2.16 32.535 41.04 32.805 ;
     RECT  2.16 33.075 41.04 33.345 ;
     RECT  2.16 33.615 41.04 33.885 ;
     RECT  2.16 34.155 41.04 34.425 ;
     RECT  2.16 34.695 41.04 34.965 ;
     RECT  2.16 35.235 41.04 35.505 ;
     RECT  2.16 35.775 41.04 36.045 ;
     RECT  2.16 36.315 41.04 36.585 ;
     RECT  2.16 36.855 41.04 37.125 ;
     RECT  2.16 37.395 41.04 37.665 ;
     RECT  2.16 37.935 41.04 38.205 ;
     RECT  2.16 38.475 41.04 38.745 ;
     RECT  2.16 39.015 41.04 39.285 ;
     RECT  2.16 39.555 41.04 39.825 ;
     RECT  2.16 40.095 41.04 40.365 ;
     RECT  2.16 40.635 41.04 40.905 ;
    LAYER M1 ;
     RECT  2.16 2.151 41.04 41.049 ;
    LAYER M2 ;
     RECT  0.031 14.076 0.103 14.094 ;
     RECT  0.103 13.266 0.139 13.284 ;
     RECT  0.103 14.076 0.139 14.706 ;
     RECT  0.103 10.206 0.203 10.224 ;
     RECT  0.103 40.176 0.203 40.194 ;
     RECT  0.103 22.896 0.319 22.914 ;
     RECT  0.139 28.026 0.319 28.044 ;
     RECT  0.103 29.106 0.319 29.124 ;
     RECT  0.103 25.866 0.355 25.884 ;
     RECT  0.103 20.826 0.391 21.024 ;
     RECT  0.319 22.896 0.391 23.544 ;
     RECT  0.103 31.806 0.391 31.824 ;
     RECT  0.355 25.056 0.427 25.884 ;
     RECT  0.391 26.766 0.427 26.784 ;
     RECT  0.139 15.876 0.463 15.894 ;
     RECT  0.391 31.806 0.463 32.364 ;
     RECT  0.139 18.576 0.499 18.594 ;
     RECT  0.391 20.826 0.499 21.564 ;
     RECT  0.391 22.896 0.499 24.156 ;
     RECT  0.103 30.348 0.499 30.366 ;
     RECT  0.427 24.912 0.527 26.784 ;
     RECT  0.139 13.266 0.535 14.706 ;
     RECT  0.463 15.498 0.535 15.894 ;
     RECT  0.499 18.396 0.535 18.594 ;
     RECT  0.499 20.358 0.535 21.564 ;
     RECT  0.499 22.788 0.535 24.156 ;
     RECT  0.319 28.026 0.535 29.124 ;
     RECT  0.499 30.348 0.535 30.834 ;
     RECT  0.463 31.626 0.535 32.364 ;
     RECT  0.463 33.282 0.535 33.3 ;
     RECT  0.499 34.056 0.535 34.074 ;
     RECT  0.527 24.984 0.563 26.784 ;
     RECT  2.011 5.004 2.16 5.022 ;
     RECT  0.103 8.172 2.16 8.19 ;
     RECT  0.103 11.916 2.16 11.934 ;
     RECT  0.535 13.266 2.16 15.894 ;
     RECT  0.427 16.884 2.16 16.902 ;
     RECT  0.535 18.126 2.16 18.594 ;
     RECT  0.535 20.088 2.16 24.156 ;
     RECT  0.563 25.326 2.16 26.784 ;
     RECT  0.535 27.918 2.16 32.364 ;
     RECT  0.535 33.246 2.16 33.3 ;
     RECT  0.535 34.056 2.16 34.416 ;
     RECT  0.535 35.208 2.16 35.226 ;
     RECT  0.535 37.908 2.16 37.926 ;
     RECT  0.103 38.826 2.16 38.844 ;
     RECT  2.16 2.151 3.343 41.049 ;
     RECT  3.343 2.106 3.883 41.049 ;
     RECT  3.883 2.034 5.603 41.049 ;
     RECT  5.603 2.106 6.935 41.049 ;
     RECT  6.935 2.151 41.04 41.049 ;
     RECT  41.04 7.596 41.063 27.36 ;
     RECT  41.04 28.224 41.567 28.476 ;
     RECT  41.04 2.196 41.603 5.994 ;
     RECT  41.063 7.596 41.603 17.37 ;
     RECT  41.063 18.198 41.603 21.834 ;
     RECT  41.063 22.788 41.603 27.36 ;
     RECT  41.567 28.224 41.603 28.278 ;
     RECT  41.603 2.196 41.639 2.79 ;
     RECT  41.603 12.294 41.639 13.554 ;
     RECT  41.603 14.418 41.639 17.37 ;
     RECT  41.603 19.08 41.639 19.764 ;
     RECT  41.603 23.13 41.639 27.36 ;
     RECT  41.04 30.42 41.639 32.49 ;
     RECT  41.04 33.318 41.639 40.968 ;
     RECT  41.639 2.232 41.711 2.754 ;
     RECT  41.639 12.294 41.927 13.428 ;
     RECT  41.927 12.294 42.143 13.194 ;
     RECT  41.711 2.736 42.179 2.754 ;
     RECT  41.603 3.546 42.179 5.994 ;
     RECT  41.04 6.786 42.179 6.84 ;
     RECT  41.603 7.596 42.179 9.774 ;
     RECT  42.143 12.294 42.179 12.348 ;
     RECT  42.143 13.176 42.179 13.194 ;
     RECT  41.639 23.976 42.179 27.36 ;
     RECT  41.04 29.268 42.179 29.628 ;
     RECT  41.639 34.128 42.179 40.968 ;
     RECT  42.179 3.546 42.215 3.564 ;
     RECT  42.179 4.626 42.215 5.994 ;
     RECT  42.179 7.596 42.215 7.884 ;
     RECT  41.603 10.71 42.215 11.538 ;
     RECT  42.179 12.33 42.215 12.348 ;
     RECT  41.639 14.418 42.215 17.1 ;
     RECT  41.603 20.736 42.215 21.834 ;
     RECT  41.639 23.13 42.215 23.184 ;
     RECT  42.179 23.976 42.215 23.994 ;
     RECT  42.179 26.064 42.215 27.36 ;
     RECT  41.603 28.26 42.215 28.278 ;
     RECT  41.639 30.42 42.215 32.328 ;
     RECT  42.179 36.252 42.215 36.648 ;
     RECT  42.179 37.872 42.215 37.89 ;
     RECT  42.179 39.096 42.215 40.968 ;
     RECT  42.215 20.736 42.251 21.726 ;
     RECT  42.251 21.708 43.043 21.726 ;
     RECT  42.215 26.568 43.043 27.36 ;
     RECT  41.639 33.318 43.043 33.336 ;
     RECT  42.179 35.478 43.043 35.496 ;
     RECT  42.215 14.418 43.079 16.704 ;
     RECT  42.215 30.42 43.079 31.212 ;
     RECT  42.215 5.166 43.115 5.724 ;
     RECT  42.179 6.786 43.115 6.804 ;
     RECT  42.215 7.596 43.115 7.614 ;
     RECT  42.179 9.216 43.115 9.774 ;
     RECT  42.215 10.71 43.115 10.728 ;
     RECT  42.215 11.52 43.115 11.538 ;
     RECT  43.079 14.418 43.115 16.632 ;
     RECT  41.603 18.198 43.115 18.216 ;
     RECT  41.639 19.08 43.115 19.098 ;
     RECT  42.251 20.736 43.115 20.754 ;
     RECT  42.215 23.13 43.115 23.148 ;
     RECT  42.179 25.182 43.115 25.2 ;
     RECT  43.043 26.874 43.115 27.36 ;
     RECT  42.179 29.268 43.115 29.556 ;
     RECT  43.079 30.42 43.115 30.438 ;
     RECT  43.079 31.194 43.115 31.212 ;
     RECT  42.215 36.252 43.115 36.27 ;
     RECT  42.215 39.096 43.115 39.114 ;
     RECT  42.215 40.176 43.115 40.194 ;
     RECT  42.215 40.95 43.115 40.968 ;
    LAYER M3 ;
     RECT  3.888 2.029 3.906 2.101 ;
     RECT  5.58 2.029 5.598 2.101 ;
     RECT  18.615 2.143 18.705 2.191 ;
     RECT  5.148 2.101 5.598 2.219 ;
     RECT  41.616 2.191 41.634 2.227 ;
     RECT  2.415 2.143 2.505 2.251 ;
     RECT  5.4 2.219 5.598 2.263 ;
     RECT  5.4 2.263 5.742 2.291 ;
     RECT  2.304 2.251 2.505 2.413 ;
     RECT  3.348 2.101 4.374 2.413 ;
     RECT  7.815 2.143 7.905 2.413 ;
     RECT  13.215 2.143 13.305 2.413 ;
     RECT  18.615 2.191 18.882 2.413 ;
     RECT  24.015 2.143 24.105 2.413 ;
     RECT  29.415 2.143 29.505 2.413 ;
     RECT  34.815 2.143 34.905 2.413 ;
     RECT  40.215 2.143 40.305 2.413 ;
     RECT  0.108 2.347 0.126 2.477 ;
     RECT  6.912 2.101 6.93 2.569 ;
     RECT  41.616 2.227 41.706 2.635 ;
     RECT  5.724 2.291 5.742 2.641 ;
     RECT  2.304 2.413 4.374 2.759 ;
     RECT  5.724 2.641 5.994 2.759 ;
     RECT  6.912 2.569 7.074 2.759 ;
     RECT  41.616 2.635 42.174 2.759 ;
     RECT  21.96 2.191 21.978 2.767 ;
     RECT  21.924 2.767 21.978 2.768 ;
     RECT  22.824 2.641 22.842 2.795 ;
     RECT  3.636 2.759 4.374 2.861 ;
     RECT  21.924 2.768 21.942 2.939 ;
     RECT  40.215 2.413 40.497 3.001 ;
     RECT  41.616 2.759 41.634 3.001 ;
     RECT  4.032 2.861 4.374 3.181 ;
     RECT  6.876 2.767 6.894 3.181 ;
     RECT  4.032 3.181 4.554 3.271 ;
     RECT  6.804 3.181 6.894 3.299 ;
     RECT  6.876 3.299 6.894 3.335 ;
     RECT  40.215 3.001 41.634 3.335 ;
     RECT  20.412 3.271 20.43 3.371 ;
     RECT  4.032 3.271 4.626 3.407 ;
     RECT  21.492 3.271 21.51 3.407 ;
     RECT  42.156 3.541 42.21 3.581 ;
     RECT  5.724 2.759 5.742 3.685 ;
     RECT  4.032 3.407 4.374 3.721 ;
     RECT  22.68 3.307 22.698 3.721 ;
     RECT  5.292 3.685 5.742 3.749 ;
     RECT  5.292 3.749 5.598 3.839 ;
     RECT  22.572 3.721 23.022 3.839 ;
     RECT  3.96 3.721 4.374 3.875 ;
     RECT  23.004 3.839 23.022 3.875 ;
     RECT  2.304 2.759 2.697 3.931 ;
     RECT  21.204 3.685 21.402 4.081 ;
     RECT  40.215 3.335 41.058 4.081 ;
     RECT  42.156 3.581 42.174 4.081 ;
     RECT  3.96 3.875 4.158 4.109 ;
     RECT  4.14 4.109 4.158 4.157 ;
     RECT  40.215 4.081 42.174 4.157 ;
     RECT  21.168 4.081 21.402 4.351 ;
     RECT  42.156 4.157 42.174 4.379 ;
     RECT  21.168 4.351 22.014 4.451 ;
     RECT  2.304 3.931 2.898 4.507 ;
     RECT  21.168 4.451 21.906 4.721 ;
     RECT  42.192 4.621 42.21 4.733 ;
     RECT  40.215 4.157 41.022 4.885 ;
     RECT  21.168 4.721 21.51 4.891 ;
     RECT  5.472 3.839 5.598 4.919 ;
     RECT  40.215 4.885 41.058 4.925 ;
     RECT  5.58 4.919 5.598 4.927 ;
     RECT  5.58 4.927 5.814 4.955 ;
     RECT  21.132 4.891 21.51 4.991 ;
     RECT  2.304 4.507 3.114 4.999 ;
     RECT  4.5 4.742 4.518 4.999 ;
     RECT  2.016 4.999 3.114 5.083 ;
     RECT  3.996 4.999 4.518 5.083 ;
     RECT  2.016 5.083 4.518 5.117 ;
     RECT  5.796 4.955 5.814 5.189 ;
     RECT  21.168 4.991 21.51 5.261 ;
     RECT  2.304 5.117 4.518 5.269 ;
     RECT  2.304 5.269 4.698 5.459 ;
     RECT  20.412 5.305 20.43 5.459 ;
     RECT  21.168 5.261 21.366 5.459 ;
     RECT  2.304 5.459 4.518 5.495 ;
     RECT  41.616 5.197 41.634 5.501 ;
     RECT  2.415 5.495 4.518 5.693 ;
     RECT  43.092 5.083 43.11 5.729 ;
     RECT  2.415 5.693 4.014 5.741 ;
     RECT  21.168 5.459 21.186 5.801 ;
     RECT  18.615 2.413 18.897 5.881 ;
     RECT  37.584 5.851 37.602 5.909 ;
     RECT  23.112 5.881 23.13 5.971 ;
     RECT  2.415 5.741 2.826 5.999 ;
     RECT  3.744 5.741 4.014 5.999 ;
     RECT  6.876 4.531 6.894 5.999 ;
     RECT  18.615 5.881 19.494 5.999 ;
     RECT  23.112 5.971 23.202 6.007 ;
     RECT  24.015 2.413 24.297 6.007 ;
     RECT  22.5 6.007 24.297 6.043 ;
     RECT  37.62 6.007 37.638 6.077 ;
     RECT  18.615 5.999 18.954 6.179 ;
     RECT  20.52 5.971 21.114 6.179 ;
     RECT  22.32 6.043 24.297 6.179 ;
     RECT  2.415 5.999 2.697 6.235 ;
     RECT  40.215 4.925 40.497 6.241 ;
     RECT  20.628 6.179 21.114 6.269 ;
     RECT  42.192 5.971 42.21 6.269 ;
     RECT  39.924 6.241 40.497 6.317 ;
     RECT  22.32 6.179 22.482 6.385 ;
     RECT  2.412 6.235 2.697 6.427 ;
     RECT  2.304 6.427 2.697 6.808 ;
     RECT  3.888 5.999 4.014 6.809 ;
     RECT  20.628 6.269 20.718 6.809 ;
     RECT  43.092 6.619 43.11 6.809 ;
     RECT  5.796 6.421 5.814 6.817 ;
     RECT  2.304 6.808 2.97 6.845 ;
     RECT  42.156 6.808 42.174 6.845 ;
     RECT  7.815 2.413 8.097 6.961 ;
     RECT  22.068 6.385 22.482 6.989 ;
     RECT  40.215 6.317 40.497 7.003 ;
     RECT  5.616 6.817 5.814 7.051 ;
     RECT  7.128 6.961 8.097 7.051 ;
     RECT  40.215 7.003 41.022 7.051 ;
     RECT  7.128 7.051 8.19 7.087 ;
     RECT  18.615 6.179 18.897 7.087 ;
     RECT  6.912 7.087 8.19 7.115 ;
     RECT  39.924 7.051 41.022 7.115 ;
     RECT  5.616 7.051 6.174 7.123 ;
     RECT  5.544 7.123 6.174 7.151 ;
     RECT  21.816 7.051 21.834 7.151 ;
     RECT  3.996 6.809 4.014 7.223 ;
     RECT  10.8 7.087 10.818 7.223 ;
     RECT  5.544 7.151 5.634 7.259 ;
     RECT  7.815 7.115 8.19 7.259 ;
     RECT  18.615 7.087 18.954 7.259 ;
     RECT  39.924 7.115 40.497 7.373 ;
     RECT  43.092 7.531 43.11 7.619 ;
     RECT  2.304 6.845 2.697 7.723 ;
     RECT  6.912 7.115 7.074 7.735 ;
     RECT  20.736 7.321 20.754 7.735 ;
     RECT  20.556 7.735 20.754 7.771 ;
     RECT  6.552 7.735 7.074 7.889 ;
     RECT  20.196 7.771 20.754 7.889 ;
     RECT  22.68 7.735 23.166 7.889 ;
     RECT  22.86 7.889 23.166 7.925 ;
     RECT  42.192 7.861 42.21 7.949 ;
     RECT  5.616 7.259 5.634 8.041 ;
     RECT  6.84 7.889 7.074 8.041 ;
     RECT  7.815 7.259 8.097 8.041 ;
     RECT  5.616 8.041 5.85 8.107 ;
     RECT  20.736 7.889 20.754 8.131 ;
     RECT  0.108 8.107 0.126 8.195 ;
     RECT  6.84 8.041 8.097 8.267 ;
     RECT  2.304 7.723 2.754 8.401 ;
     RECT  5.544 8.107 5.85 8.401 ;
     RECT  40.215 7.373 40.497 8.401 ;
     RECT  5.364 8.401 5.85 8.429 ;
     RECT  40.215 8.401 40.554 8.525 ;
     RECT  2.304 8.401 2.862 8.581 ;
     RECT  4.356 7.435 4.374 8.581 ;
     RECT  5.364 8.429 5.382 8.581 ;
     RECT  2.304 8.581 3.186 8.671 ;
     RECT  2.304 8.671 3.258 8.683 ;
     RECT  4.356 8.581 5.382 8.699 ;
     RECT  42.156 8.107 42.174 8.699 ;
     RECT  20.736 8.131 21.474 8.771 ;
     RECT  4.356 8.699 4.374 8.827 ;
     RECT  2.268 8.683 3.258 8.851 ;
     RECT  3.996 8.827 4.374 8.851 ;
     RECT  2.268 8.851 4.374 9.005 ;
     RECT  39.312 8.707 39.33 9.005 ;
     RECT  6.912 8.267 8.097 9.239 ;
     RECT  18.615 7.259 18.897 9.247 ;
     RECT  41.616 9.247 41.634 9.293 ;
     RECT  20.952 8.771 21.474 9.311 ;
     RECT  5.292 8.699 5.382 9.391 ;
     RECT  18.615 9.247 18.954 9.419 ;
     RECT  5.292 9.391 5.598 9.509 ;
     RECT  4.356 9.005 4.374 9.643 ;
     RECT  2.304 9.005 3.438 9.689 ;
     RECT  21.312 9.311 21.474 9.751 ;
     RECT  22.824 9.247 22.842 9.751 ;
     RECT  43.092 8.683 43.11 9.779 ;
     RECT  21.312 9.751 22.842 9.787 ;
     RECT  40.215 8.525 40.497 9.787 ;
     RECT  5.292 9.509 5.382 9.815 ;
     RECT  7.092 9.239 8.097 9.815 ;
     RECT  2.415 9.689 3.438 9.895 ;
     RECT  4.356 9.643 4.518 9.895 ;
     RECT  21.312 9.787 22.878 9.923 ;
     RECT  2.415 9.895 4.734 10.049 ;
     RECT  7.272 9.815 8.097 10.049 ;
     RECT  21.636 9.923 22.878 10.049 ;
     RECT  2.415 10.049 4.086 10.085 ;
     RECT  0.108 9.451 0.126 10.123 ;
     RECT  0.036 10.123 0.126 10.171 ;
     RECT  40.215 9.787 41.058 10.193 ;
     RECT  40.215 10.193 40.497 10.201 ;
     RECT  0.036 10.171 0.198 10.229 ;
     RECT  41.58 10.219 41.598 10.411 ;
     RECT  38.124 10.093 38.142 10.435 ;
     RECT  34.815 2.413 35.097 10.471 ;
     RECT  34.815 10.471 35.694 10.561 ;
     RECT  37.188 10.597 37.206 10.603 ;
     RECT  36.504 10.603 37.206 10.637 ;
     RECT  22.14 10.049 22.158 10.939 ;
     RECT  41.58 10.411 41.634 10.939 ;
     RECT  34.815 10.561 35.766 10.975 ;
     RECT  36.504 10.637 37.134 10.975 ;
     RECT  38.124 10.435 38.826 11.011 ;
     RECT  39.78 10.201 40.497 11.011 ;
     RECT  38.124 11.011 40.497 11.129 ;
     RECT  20.808 10.699 20.826 11.131 ;
     RECT  39.708 11.129 40.497 11.131 ;
     RECT  41.58 10.939 42.21 11.131 ;
     RECT  34.704 10.975 37.134 11.209 ;
     RECT  18.615 9.419 18.897 11.227 ;
     RECT  38.124 11.129 38.79 11.237 ;
     RECT  2.415 10.085 2.697 11.323 ;
     RECT  13.215 2.413 13.497 11.371 ;
     RECT  2.304 11.323 2.697 11.399 ;
     RECT  14.832 11.227 14.85 11.405 ;
     RECT  13.104 11.371 13.497 11.408 ;
     RECT  0.036 10.229 0.126 11.515 ;
     RECT  43.092 10.603 43.11 11.543 ;
     RECT  34.2 11.209 37.134 11.551 ;
     RECT  38.124 11.237 38.142 11.551 ;
     RECT  34.2 11.551 38.142 11.669 ;
     RECT  0.036 11.515 0.162 11.707 ;
     RECT  39.708 11.131 42.21 11.741 ;
     RECT  39.708 11.741 41.022 11.813 ;
     RECT  20.808 11.131 21.114 11.911 ;
     RECT  21.924 10.939 22.158 11.947 ;
     RECT  39.708 11.813 40.842 11.947 ;
     RECT  0.036 11.707 0.198 12.091 ;
     RECT  13.215 11.408 13.497 12.283 ;
     RECT  34.2 11.669 37.098 12.289 ;
     RECT  42.12 11.741 42.21 12.353 ;
     RECT  37.98 11.669 38.142 12.361 ;
     RECT  39.492 11.947 40.842 12.361 ;
     RECT  37.98 12.361 40.842 12.479 ;
     RECT  39.024 12.479 40.626 12.551 ;
     RECT  42.12 12.353 42.174 12.667 ;
     RECT  20.268 11.911 21.114 12.763 ;
     RECT  21.924 11.947 22.77 12.763 ;
     RECT  24.015 6.179 24.297 12.829 ;
     RECT  18.615 11.227 19.386 13.051 ;
     RECT  33.876 12.289 37.098 13.171 ;
     RECT  37.98 12.479 38.286 13.171 ;
     RECT  41.58 12.667 42.174 13.199 ;
     RECT  33.876 13.171 38.286 13.333 ;
     RECT  39.024 12.551 40.497 13.333 ;
     RECT  2.415 11.399 2.697 13.432 ;
     RECT  13.215 12.283 13.95 13.432 ;
     RECT  41.58 13.199 41.922 13.433 ;
     RECT  33.876 13.333 40.497 13.435 ;
     RECT  41.58 13.433 41.634 13.435 ;
     RECT  18.615 13.051 19.53 13.441 ;
     RECT  20.268 12.763 22.77 13.441 ;
     RECT  2.304 13.432 2.697 13.469 ;
     RECT  13.104 13.432 13.95 13.469 ;
     RECT  18.615 13.441 23.274 13.531 ;
     RECT  24.015 12.829 24.786 13.531 ;
     RECT  33.876 13.435 41.634 13.603 ;
     RECT  33.336 13.603 41.634 13.631 ;
     RECT  41.544 13.631 41.634 13.661 ;
     RECT  18.615 13.531 24.786 13.667 ;
     RECT  30.456 13.063 30.474 13.909 ;
     RECT  0.036 12.091 0.234 14.099 ;
     RECT  30.456 13.909 30.798 14.099 ;
     RECT  33.336 13.631 40.497 14.099 ;
     RECT  33.336 14.099 38.934 14.135 ;
     RECT  41.544 13.661 41.598 14.171 ;
     RECT  43.092 14.203 43.11 14.395 ;
     RECT  18.615 13.667 22.77 14.449 ;
     RECT  24.015 13.667 24.786 14.449 ;
     RECT  33.336 14.135 38.79 14.513 ;
     RECT  0.108 14.099 0.234 14.639 ;
     RECT  36.036 14.513 38.79 14.881 ;
     RECT  39.708 14.099 40.497 14.881 ;
     RECT  41.58 14.171 41.598 14.981 ;
     RECT  43.056 14.395 43.11 15.053 ;
     RECT  2.415 13.469 2.697 15.115 ;
     RECT  2.304 15.115 2.697 15.151 ;
     RECT  13.215 13.469 13.95 15.151 ;
     RECT  29.415 2.413 29.697 15.187 ;
     RECT  30.456 14.099 30.474 15.187 ;
     RECT  36.036 14.881 40.497 15.215 ;
     RECT  10.836 15.151 10.854 15.251 ;
     RECT  26.748 15.187 26.766 15.323 ;
     RECT  0.108 14.639 0.126 15.421 ;
     RECT  33.336 14.513 35.226 15.421 ;
     RECT  33.336 15.421 35.262 15.493 ;
     RECT  36.036 15.215 39.258 15.493 ;
     RECT  40.068 15.215 40.497 15.499 ;
     RECT  33.336 15.493 39.258 15.719 ;
     RECT  13.104 15.151 13.95 15.728 ;
     RECT  32.508 15.151 32.526 15.763 ;
     RECT  40.068 15.499 41.022 15.791 ;
     RECT  42.192 15.307 42.21 15.863 ;
     RECT  18.615 14.449 24.786 15.899 ;
     RECT  33.336 15.719 39.15 15.899 ;
     RECT  18.615 15.899 23.166 15.961 ;
     RECT  2.304 15.151 3.402 16.075 ;
     RECT  33.336 15.899 38.862 16.259 ;
     RECT  29.415 15.187 30.474 16.331 ;
     RECT  41.58 16.075 42.174 16.331 ;
     RECT  1.98 16.075 3.402 16.363 ;
     RECT  30.456 16.331 30.474 16.403 ;
     RECT  40.068 15.791 40.842 16.501 ;
     RECT  18.216 15.961 23.166 16.529 ;
     RECT  26.784 16.339 26.802 16.529 ;
     RECT  43.092 15.053 43.11 16.636 ;
     RECT  43.056 16.636 43.11 16.637 ;
     RECT  32.184 15.763 32.526 16.673 ;
     RECT  31.356 16.501 31.374 16.681 ;
     RECT  43.056 16.637 43.074 16.709 ;
     RECT  39.744 16.501 40.842 16.799 ;
     RECT  34.272 16.259 38.862 16.835 ;
     RECT  30.78 16.681 31.374 16.871 ;
     RECT  0.108 15.421 0.558 16.877 ;
     RECT  39.888 16.799 40.842 16.915 ;
     RECT  41.58 16.331 41.598 16.915 ;
     RECT  0.108 16.877 0.522 17.069 ;
     RECT  34.272 16.835 38.79 17.069 ;
     RECT  39.888 16.915 41.598 17.077 ;
     RECT  34.272 17.069 35.73 17.117 ;
     RECT  1.98 16.363 3.69 17.165 ;
     RECT  33.336 16.259 33.354 17.177 ;
     RECT  31.356 16.871 31.374 17.249 ;
     RECT  39.888 17.077 42.21 17.261 ;
     RECT  6.228 16.231 6.246 17.311 ;
     RECT  18.216 16.529 23.094 17.311 ;
     RECT  24.015 15.899 24.786 17.447 ;
     RECT  39.888 17.261 41.634 17.453 ;
     RECT  34.488 17.117 35.73 17.483 ;
     RECT  4.536 17.041 4.554 17.491 ;
     RECT  39.888 17.453 41.058 17.609 ;
     RECT  18.216 17.311 23.13 17.645 ;
     RECT  13.215 15.728 13.95 17.752 ;
     RECT  18.615 17.645 23.13 17.761 ;
     RECT  24.015 17.447 24.297 17.761 ;
     RECT  13.104 17.752 13.95 17.789 ;
     RECT  14.832 17.659 14.85 17.789 ;
     RECT  36.504 17.069 38.79 17.887 ;
     RECT  36.468 17.887 38.79 17.923 ;
     RECT  18.615 17.761 24.297 17.951 ;
     RECT  26.676 17.887 26.694 18.031 ;
     RECT  26.676 18.031 26.766 18.059 ;
     RECT  0.108 17.069 0.486 18.121 ;
     RECT  26.748 18.059 26.766 18.149 ;
     RECT  6.228 17.311 6.822 18.221 ;
     RECT  36.468 17.923 38.826 18.301 ;
     RECT  36.468 18.301 38.898 18.391 ;
     RECT  18.615 17.951 23.13 18.491 ;
     RECT  34.776 17.483 35.73 18.571 ;
     RECT  36.468 18.391 39.042 18.571 ;
     RECT  4.536 17.491 5.13 18.599 ;
     RECT  34.776 18.571 39.042 18.661 ;
     RECT  40.215 17.609 41.058 18.697 ;
     RECT  32.184 16.673 32.202 18.733 ;
     RECT  5.112 18.599 5.13 18.845 ;
     RECT  30.78 18.841 30.798 18.959 ;
     RECT  6.804 18.221 6.822 19.003 ;
     RECT  43.092 18.184 43.11 19.103 ;
     RECT  17.676 18.031 17.694 19.111 ;
     RECT  18.615 18.491 22.986 19.111 ;
     RECT  17.676 19.111 22.986 19.133 ;
     RECT  34.776 18.661 39.366 19.229 ;
     RECT  32.184 18.733 32.778 19.237 ;
     RECT  34.776 19.229 35.766 19.265 ;
     RECT  40.215 18.697 41.598 19.325 ;
     RECT  40.215 19.325 40.497 19.387 ;
     RECT  13.215 17.789 13.95 19.471 ;
     RECT  41.544 19.325 41.598 19.483 ;
     RECT  36.504 19.229 38.826 19.499 ;
     RECT  26.748 19.471 26.766 19.507 ;
     RECT  13.104 19.471 13.95 19.517 ;
     RECT  32.184 19.237 33.102 19.535 ;
     RECT  6.768 19.003 6.822 19.579 ;
     RECT  7.815 10.049 8.097 19.579 ;
     RECT  26.712 19.507 26.766 19.607 ;
     RECT  14.832 19.483 14.85 19.613 ;
     RECT  36.792 19.499 38.826 19.709 ;
     RECT  41.544 19.483 41.634 19.769 ;
     RECT  30.852 19.201 30.87 19.849 ;
     RECT  36.864 19.709 38.826 19.877 ;
     RECT  34.776 19.265 35.55 19.913 ;
     RECT  18.18 19.133 22.986 19.921 ;
     RECT  24.015 17.951 24.297 19.921 ;
     RECT  30.78 19.849 30.87 19.949 ;
     RECT  39.816 19.387 40.497 20.059 ;
     RECT  41.544 19.769 41.598 20.059 ;
     RECT  13.215 19.517 13.95 20.183 ;
     RECT  9.936 18.463 9.954 20.189 ;
     RECT  32.76 19.535 33.102 20.345 ;
     RECT  1.98 17.165 2.697 20.353 ;
     RECT  39.816 20.059 41.598 20.353 ;
     RECT  13.215 20.183 13.497 20.443 ;
     RECT  1.98 20.353 2.862 20.453 ;
     RECT  39.744 20.353 41.598 20.453 ;
     RECT  34.815 19.913 35.55 20.461 ;
     RECT  13.104 20.443 13.497 20.489 ;
     RECT  34.815 20.461 35.946 20.539 ;
     RECT  36.864 19.877 38.79 20.539 ;
     RECT  33.084 20.345 33.102 20.615 ;
     RECT  30.852 19.949 30.87 20.651 ;
     RECT  26.712 19.607 26.73 20.695 ;
     RECT  34.815 20.539 38.79 20.723 ;
     RECT  35.892 20.723 38.79 20.731 ;
     RECT  35.892 20.731 39.15 20.759 ;
     RECT  43.092 20.443 43.11 20.759 ;
     RECT  41.58 20.453 41.598 20.827 ;
     RECT  34.815 20.723 35.154 20.929 ;
     RECT  41.58 20.827 42.21 21.019 ;
     RECT  18.18 19.921 24.297 21.029 ;
     RECT  26.712 20.695 26.766 21.029 ;
     RECT  0.108 18.121 0.558 21.053 ;
     RECT  26.712 21.029 26.73 21.091 ;
     RECT  11.664 10.603 11.682 21.119 ;
     RECT  34.776 20.929 35.154 21.163 ;
     RECT  26.64 21.091 26.73 21.191 ;
     RECT  36.684 20.759 39.15 21.259 ;
     RECT  41.58 21.019 42.246 21.263 ;
     RECT  36.684 21.259 39.258 21.425 ;
     RECT  6.768 19.579 8.097 21.437 ;
     RECT  26.676 21.191 26.73 21.461 ;
     RECT  41.58 21.263 42.21 21.461 ;
     RECT  36.684 21.425 39.114 21.497 ;
     RECT  34.344 21.163 35.154 21.499 ;
     RECT  35.892 20.759 35.946 21.499 ;
     RECT  31.356 21.397 31.446 21.569 ;
     RECT  34.128 21.499 35.946 21.631 ;
     RECT  36.684 21.497 39.042 21.631 ;
     RECT  43.02 21.595 43.038 21.731 ;
     RECT  40.215 20.453 40.497 21.787 ;
     RECT  10.8 19.201 10.818 21.821 ;
     RECT  18.615 21.029 24.297 21.937 ;
     RECT  34.128 21.631 39.042 21.937 ;
     RECT  42.192 21.461 42.21 22.013 ;
     RECT  40.215 21.787 41.022 22.045 ;
     RECT  1.98 20.453 2.697 22.109 ;
     RECT  7.38 21.437 8.097 22.205 ;
     RECT  33.876 21.937 39.042 22.205 ;
     RECT  2.304 22.109 2.697 22.208 ;
     RECT  18.216 21.937 24.297 22.307 ;
     RECT  40.176 22.045 41.022 22.351 ;
     RECT  40.176 22.351 41.058 22.363 ;
     RECT  33.12 22.243 33.138 22.468 ;
     RECT  33.084 22.468 33.138 22.477 ;
     RECT  33.876 22.205 35.097 22.477 ;
     RECT  26.712 21.461 26.73 22.541 ;
     RECT  35.928 22.205 39.042 22.585 ;
     RECT  3.672 17.165 3.69 22.649 ;
     RECT  0.396 21.053 0.558 22.891 ;
     RECT  35.928 22.585 39.114 22.891 ;
     RECT  40.176 22.363 41.598 22.891 ;
     RECT  18.216 22.307 19.926 22.919 ;
     RECT  0.108 22.891 0.558 22.928 ;
     RECT  35.928 22.891 41.598 22.987 ;
     RECT  18.615 22.919 19.926 23.125 ;
     RECT  20.7 22.307 24.297 23.125 ;
     RECT  43.092 22.555 43.11 23.153 ;
     RECT  33.084 22.477 35.097 23.161 ;
     RECT  35.892 22.987 41.598 23.161 ;
     RECT  18.615 23.125 24.297 23.279 ;
     RECT  26.748 23.125 26.766 23.315 ;
     RECT  33.084 23.161 42.21 23.323 ;
     RECT  32.508 23.323 42.21 23.729 ;
     RECT  33.84 23.729 42.21 23.927 ;
     RECT  0.324 22.928 0.558 23.947 ;
     RECT  0.108 23.947 0.558 24.077 ;
     RECT  18.615 23.279 19.818 24.241 ;
     RECT  41.58 23.927 42.21 24.269 ;
     RECT  33.84 23.927 40.842 24.509 ;
     RECT  32.508 23.729 32.526 24.709 ;
     RECT  33.876 24.509 40.842 24.709 ;
     RECT  41.58 24.269 42.174 24.709 ;
     RECT  13.215 20.489 13.497 24.763 ;
     RECT  2.415 22.208 2.697 24.781 ;
     RECT  14.832 24.667 14.85 24.797 ;
     RECT  13.104 24.763 13.497 24.809 ;
     RECT  32.508 24.709 33.102 24.809 ;
     RECT  2.304 24.781 2.697 24.845 ;
     RECT  33.876 24.709 42.174 24.845 ;
     RECT  0.324 24.077 0.558 25.085 ;
     RECT  18.615 24.241 19.926 25.141 ;
     RECT  20.808 23.279 24.297 25.141 ;
     RECT  43.092 25.003 43.11 25.205 ;
     RECT  41.616 24.845 42.174 25.229 ;
     RECT  18.615 25.141 24.297 25.241 ;
     RECT  30.456 21.973 30.474 25.277 ;
     RECT  26.316 25.195 26.334 25.411 ;
     RECT  26.316 25.411 26.766 25.439 ;
     RECT  26.748 25.439 26.766 25.469 ;
     RECT  20.736 25.241 24.297 25.475 ;
     RECT  21.168 25.475 24.297 25.517 ;
     RECT  42.156 25.229 42.174 25.579 ;
     RECT  33.876 24.845 40.842 25.619 ;
     RECT  33.876 25.619 35.097 25.675 ;
     RECT  0.36 25.085 0.558 25.861 ;
     RECT  2.415 24.845 2.697 25.951 ;
     RECT  13.215 24.809 13.497 25.951 ;
     RECT  42.156 25.579 42.21 25.963 ;
     RECT  33.84 25.675 35.097 26.015 ;
     RECT  18.615 25.241 19.926 26.023 ;
     RECT  41.58 25.963 42.21 26.087 ;
     RECT  18.615 26.023 19.998 26.159 ;
     RECT  0.108 25.861 0.558 26.189 ;
     RECT  31.356 21.569 31.374 26.285 ;
     RECT  21.204 25.517 24.297 26.393 ;
     RECT  33.912 26.015 35.097 26.491 ;
     RECT  43.092 26.347 43.11 26.491 ;
     RECT  14.832 25.819 14.85 26.525 ;
     RECT  2.304 25.951 2.697 26.528 ;
     RECT  13.104 25.951 13.497 26.528 ;
     RECT  43.02 26.491 43.11 26.591 ;
     RECT  33.912 26.491 35.19 26.761 ;
     RECT  35.928 25.619 40.842 26.761 ;
     RECT  41.58 26.087 41.598 26.875 ;
     RECT  0.36 26.189 0.558 26.909 ;
     RECT  41.58 26.875 42.174 26.933 ;
     RECT  0.36 26.909 0.522 27.163 ;
     RECT  0.108 27.163 0.522 27.293 ;
     RECT  33.912 26.761 40.842 27.329 ;
     RECT  43.092 26.591 43.11 27.365 ;
     RECT  34.344 27.329 40.842 27.451 ;
     RECT  21.276 26.393 24.297 27.481 ;
     RECT  20.664 27.481 24.297 27.599 ;
     RECT  42.156 26.933 42.174 27.835 ;
     RECT  0.36 27.293 0.522 27.913 ;
     RECT  34.344 27.451 41.022 27.917 ;
     RECT  14.832 27.841 14.85 27.941 ;
     RECT  26.748 27.031 26.766 27.941 ;
     RECT  0.36 27.913 0.558 28.021 ;
     RECT  34.416 27.917 41.022 28.027 ;
     RECT  42.156 27.835 42.21 28.027 ;
     RECT  18.615 26.159 19.926 28.049 ;
     RECT  28.512 27.211 28.53 28.049 ;
     RECT  0.144 28.021 0.558 28.061 ;
     RECT  29.415 16.331 29.697 28.183 ;
     RECT  34.416 28.027 42.21 28.283 ;
     RECT  34.416 28.283 41.562 28.481 ;
     RECT  18.615 28.049 19.602 28.831 ;
     RECT  18.615 28.831 19.998 28.921 ;
     RECT  0.324 28.061 0.558 29.021 ;
     RECT  20.736 27.599 24.297 29.021 ;
     RECT  34.416 28.481 41.022 29.021 ;
     RECT  0.324 29.021 0.522 29.101 ;
     RECT  18.216 28.921 19.998 29.129 ;
     RECT  29.088 28.183 29.697 29.129 ;
     RECT  19.98 29.129 19.998 29.255 ;
     RECT  18.216 29.129 18.954 29.263 ;
     RECT  42.192 29.179 42.21 29.362 ;
     RECT  42.156 29.362 42.21 29.363 ;
     RECT  0.108 29.101 0.522 29.405 ;
     RECT  42.156 29.363 42.174 29.633 ;
     RECT  18.144 29.263 18.954 29.731 ;
     RECT  0.432 29.405 0.522 29.803 ;
     RECT  2.415 26.528 2.697 29.899 ;
     RECT  2.415 29.899 2.79 29.939 ;
     RECT  18.108 29.731 18.954 29.939 ;
     RECT  34.416 29.021 40.842 30.331 ;
     RECT  0.432 29.803 0.558 30.343 ;
     RECT  34.416 30.331 41.022 30.641 ;
     RECT  33.624 30.181 33.642 30.685 ;
     RECT  21.276 29.021 24.297 30.721 ;
     RECT  33.084 30.685 33.642 30.911 ;
     RECT  30.672 30.811 30.798 30.941 ;
     RECT  18.108 29.939 18.897 30.989 ;
     RECT  43.092 28.795 43.11 31.051 ;
     RECT  26.748 31.081 26.766 31.181 ;
     RECT  43.056 31.051 43.11 31.181 ;
     RECT  43.092 31.181 43.11 31.217 ;
     RECT  42.156 30.475 42.174 31.243 ;
     RECT  33.084 30.911 33.102 31.415 ;
     RECT  41.58 31.243 42.174 31.423 ;
     RECT  26.712 31.387 26.73 31.487 ;
     RECT  30.78 30.941 30.798 31.649 ;
     RECT  21.168 30.721 24.297 31.729 ;
     RECT  18.576 30.989 18.897 31.891 ;
     RECT  34.416 30.641 40.842 31.955 ;
     RECT  21.024 31.729 24.297 32.063 ;
     RECT  39.924 31.955 40.842 32.203 ;
     RECT  41.58 31.423 42.21 32.203 ;
     RECT  21.096 32.063 24.297 32.225 ;
     RECT  18.576 31.891 19.422 32.269 ;
     RECT  0.108 30.343 0.558 32.429 ;
     RECT  34.416 31.955 39.078 32.495 ;
     RECT  39.924 32.203 42.21 32.495 ;
     RECT  40.215 32.495 42.21 32.621 ;
     RECT  40.215 32.621 41.634 32.813 ;
     RECT  18.216 32.269 19.422 32.971 ;
     RECT  40.215 32.813 41.598 33.005 ;
     RECT  21.204 32.225 24.297 33.305 ;
     RECT  40.215 33.005 40.842 33.313 ;
     RECT  43.02 33.313 43.038 33.389 ;
     RECT  18.18 32.971 19.422 33.581 ;
     RECT  34.416 32.495 36.882 33.691 ;
     RECT  37.872 32.495 39.078 33.691 ;
     RECT  40.176 33.313 40.842 33.691 ;
     RECT  41.58 33.005 41.598 33.739 ;
     RECT  0.396 32.429 0.558 33.773 ;
     RECT  34.416 33.691 39.078 33.853 ;
     RECT  40.068 33.691 40.842 33.931 ;
     RECT  41.58 33.739 42.174 33.931 ;
     RECT  40.068 33.931 42.174 33.961 ;
     RECT  18.18 33.581 18.954 33.965 ;
     RECT  34.416 33.853 39.114 34.079 ;
     RECT  39.852 33.961 42.174 34.079 ;
     RECT  18.615 33.965 18.954 34.157 ;
     RECT  21.276 33.305 24.297 34.195 ;
     RECT  17.064 33.511 17.082 34.357 ;
     RECT  16.488 34.357 17.082 34.493 ;
     RECT  20.988 34.195 24.297 34.663 ;
     RECT  40.215 34.079 42.174 34.685 ;
     RECT  34.416 34.079 36.882 34.799 ;
     RECT  0.468 33.773 0.558 34.877 ;
     RECT  35.928 34.799 36.882 35.069 ;
     RECT  37.62 34.079 39.078 35.069 ;
     RECT  16.488 34.493 16.506 35.261 ;
     RECT  33.084 34.969 33.102 35.269 ;
     RECT  34.416 34.799 35.19 35.269 ;
     RECT  33.084 35.269 35.19 35.309 ;
     RECT  20.52 34.663 24.297 35.311 ;
     RECT  18.615 34.157 18.897 35.401 ;
     RECT  43.02 35.227 43.038 35.501 ;
     RECT  20.484 35.311 24.297 35.545 ;
     RECT  13.215 26.528 13.497 35.563 ;
     RECT  2.415 29.939 2.697 35.581 ;
     RECT  18.504 35.401 18.897 35.581 ;
     RECT  19.836 35.545 24.297 35.581 ;
     RECT  33.084 35.309 33.102 35.581 ;
     RECT  38.052 35.069 39.078 35.581 ;
     RECT  40.215 34.685 41.022 35.581 ;
     RECT  18.504 35.581 24.297 35.597 ;
     RECT  13.104 35.563 13.497 35.609 ;
     RECT  26.748 35.401 26.766 35.609 ;
     RECT  38.052 35.581 41.022 35.611 ;
     RECT  42.156 34.685 42.174 35.611 ;
     RECT  2.304 35.581 2.697 35.645 ;
     RECT  18.615 35.597 24.297 35.699 ;
     RECT  20.304 35.699 24.297 35.771 ;
     RECT  34.416 35.309 35.19 35.941 ;
     RECT  35.928 35.069 36.054 35.941 ;
     RECT  36.864 35.069 36.882 35.941 ;
     RECT  0.54 34.877 0.558 36.029 ;
     RECT  32.508 35.581 33.102 36.041 ;
     RECT  33.084 36.041 33.102 36.049 ;
     RECT  34.416 35.941 37.134 36.049 ;
     RECT  38.052 35.611 42.174 36.049 ;
     RECT  34.416 36.049 42.174 36.077 ;
     RECT  33.084 36.049 33.606 36.149 ;
     RECT  0.108 36.091 0.126 36.221 ;
     RECT  43.092 36.187 43.11 36.275 ;
     RECT  33.156 36.149 33.606 36.311 ;
     RECT  41.58 36.077 42.174 36.379 ;
     RECT  26.748 36.481 26.766 36.617 ;
     RECT  34.416 36.077 40.842 36.617 ;
     RECT  18.615 35.699 19.458 36.653 ;
     RECT  41.58 36.379 42.21 36.653 ;
     RECT  2.415 35.645 2.697 36.751 ;
     RECT  13.215 35.609 13.497 36.751 ;
     RECT  20.52 35.771 24.297 36.751 ;
     RECT  2.304 36.751 2.697 36.797 ;
     RECT  13.104 36.751 13.497 36.797 ;
     RECT  14.832 36.283 14.85 36.797 ;
     RECT  33.588 36.311 33.606 36.959 ;
     RECT  34.416 36.617 37.674 37.021 ;
     RECT  29.415 29.129 29.697 37.165 ;
     RECT  38.628 36.617 40.842 37.319 ;
     RECT  40.104 37.319 40.842 37.339 ;
     RECT  41.58 36.653 42.174 37.339 ;
     RECT  20.484 36.751 24.297 37.363 ;
     RECT  26.676 37.291 26.694 37.363 ;
     RECT  26.676 37.363 26.766 37.391 ;
     RECT  33.084 37.201 33.102 37.391 ;
     RECT  40.104 37.339 42.174 37.391 ;
     RECT  19.944 37.363 24.297 37.427 ;
     RECT  0.108 37.435 0.126 37.565 ;
     RECT  34.092 37.021 37.674 37.589 ;
     RECT  26.748 37.391 26.766 37.625 ;
     RECT  2.415 36.797 2.697 37.723 ;
     RECT  13.215 36.797 13.497 37.723 ;
     RECT  2.304 37.723 2.697 37.769 ;
     RECT  13.104 37.723 13.497 37.769 ;
     RECT  41.58 37.391 42.174 37.867 ;
     RECT  19.944 37.427 22.518 37.895 ;
     RECT  41.58 37.867 42.21 37.949 ;
     RECT  18.615 36.653 18.897 38.011 ;
     RECT  38.7 37.319 39.33 38.039 ;
     RECT  37.764 37.903 37.926 38.281 ;
     RECT  38.7 38.039 39.078 38.281 ;
     RECT  40.104 37.391 40.842 38.281 ;
     RECT  0.54 37.903 0.558 38.285 ;
     RECT  20.232 37.895 22.518 38.371 ;
     RECT  23.292 37.427 24.297 38.371 ;
     RECT  32.508 38.101 32.526 38.399 ;
     RECT  18.615 38.011 19.422 38.429 ;
     RECT  34.092 37.589 36.882 38.443 ;
     RECT  37.764 38.281 39.078 38.443 ;
     RECT  2.415 37.769 2.697 38.539 ;
     RECT  20.232 38.371 24.297 38.543 ;
     RECT  41.58 37.949 42.174 38.543 ;
     RECT  14.832 38.395 14.85 38.573 ;
     RECT  2.415 38.539 2.79 38.579 ;
     RECT  39.816 38.281 40.842 38.635 ;
     RECT  41.58 38.543 41.634 38.635 ;
     RECT  34.092 38.443 39.078 38.669 ;
     RECT  0.108 38.821 0.126 38.861 ;
     RECT  22.392 38.543 24.297 38.939 ;
     RECT  18.615 38.429 19.386 39.053 ;
     RECT  20.232 38.543 21.654 39.091 ;
     RECT  36 38.669 39.078 39.115 ;
     RECT  39.816 38.635 41.634 39.115 ;
     RECT  43.092 39.019 43.11 39.119 ;
     RECT  20.196 39.091 21.654 39.289 ;
     RECT  22.392 38.939 22.41 39.289 ;
     RECT  13.215 37.769 13.497 39.352 ;
     RECT  28.512 39.325 28.53 39.355 ;
     RECT  2.415 38.579 2.697 39.361 ;
     RECT  20.196 39.289 22.41 39.389 ;
     RECT  23.184 38.939 24.297 39.389 ;
     RECT  2.304 39.361 2.697 39.437 ;
     RECT  36 39.115 41.634 39.437 ;
     RECT  27.792 39.355 28.53 39.479 ;
     RECT  33.084 39.361 33.102 39.479 ;
     RECT  36 39.437 40.842 39.479 ;
     RECT  28.512 39.479 28.53 39.485 ;
     RECT  20.232 39.389 22.41 39.629 ;
     RECT  36 39.479 37.89 39.749 ;
     RECT  38.736 39.479 40.842 39.749 ;
     RECT  20.448 39.629 22.41 39.785 ;
     RECT  41.58 39.437 41.634 39.793 ;
     RECT  17.64 39.361 17.658 39.821 ;
     RECT  21.456 39.785 22.41 39.865 ;
     RECT  23.184 39.389 23.202 39.865 ;
     RECT  2.415 39.437 2.697 39.883 ;
     RECT  34.092 38.669 35.097 39.883 ;
     RECT  36 39.749 36.126 39.883 ;
     RECT  18.615 39.053 19.35 39.901 ;
     RECT  34.092 39.883 36.126 39.917 ;
     RECT  13.104 39.352 13.497 39.929 ;
     RECT  41.58 39.793 42.21 40.013 ;
     RECT  18.615 39.901 19.386 40.055 ;
     RECT  2.415 39.883 2.862 40.109 ;
     RECT  0.108 39.979 0.126 40.123 ;
     RECT  37.872 39.749 37.89 40.127 ;
     RECT  0.108 40.123 0.198 40.199 ;
     RECT  0.108 40.199 0.126 40.208 ;
     RECT  29.415 37.165 29.898 40.289 ;
     RECT  34.092 39.917 36.054 40.289 ;
     RECT  38.772 39.749 40.842 40.289 ;
     RECT  41.58 40.013 42.174 40.363 ;
     RECT  21.456 39.865 23.202 40.369 ;
     RECT  24.015 39.389 24.297 40.369 ;
     RECT  18.615 40.055 18.954 40.397 ;
     RECT  34.092 40.289 35.334 40.433 ;
     RECT  38.772 40.289 40.497 40.433 ;
     RECT  38.772 40.433 39.078 40.531 ;
     RECT  38.736 40.531 39.078 40.559 ;
     RECT  40.068 40.433 40.497 40.559 ;
     RECT  21.456 40.369 24.297 40.589 ;
     RECT  21.636 40.589 24.297 40.595 ;
     RECT  38.736 40.559 38.754 40.597 ;
     RECT  37.008 39.749 37.026 40.603 ;
     RECT  33.12 40.555 33.138 40.631 ;
     RECT  36.936 40.603 37.026 40.637 ;
     RECT  38.088 40.597 38.754 40.637 ;
     RECT  34.092 40.433 35.097 40.667 ;
     RECT  41.544 40.363 42.174 40.667 ;
     RECT  33.912 40.675 33.93 40.711 ;
     RECT  36.936 40.637 36.954 40.711 ;
     RECT  20.448 39.785 20.538 40.733 ;
     RECT  2.415 40.109 2.79 40.739 ;
     RECT  38.52 40.637 38.754 40.739 ;
     RECT  2.415 40.739 2.697 40.787 ;
     RECT  7.815 22.205 8.097 40.787 ;
     RECT  13.215 39.929 13.497 40.787 ;
     RECT  18.615 40.397 18.897 40.787 ;
     RECT  24.015 40.595 24.297 40.787 ;
     RECT  29.415 40.289 29.697 40.787 ;
     RECT  34.815 40.667 35.097 40.787 ;
     RECT  40.215 40.559 40.497 40.787 ;
     RECT  21.636 40.595 23.166 40.829 ;
     RECT  33.3 40.711 33.93 40.829 ;
     RECT  21.636 40.829 21.87 40.865 ;
     RECT  22.608 40.829 23.166 40.865 ;
     RECT  36.324 40.711 36.954 40.865 ;
     RECT  38.52 40.739 38.538 40.937 ;
     RECT  19.944 40.801 19.962 40.973 ;
     RECT  21.636 40.865 21.654 40.973 ;
     RECT  22.68 40.865 23.166 40.973 ;
     RECT  42.192 40.909 42.21 40.973 ;
     RECT  43.092 40.171 43.11 40.973 ;
     RECT  33.3 40.829 33.318 41.009 ;
     RECT  2.415 40.787 2.505 41.057 ;
     RECT  7.815 40.787 7.905 41.057 ;
     RECT  13.215 40.787 13.305 41.057 ;
     RECT  18.615 40.787 18.705 41.057 ;
     RECT  24.015 40.787 24.105 41.057 ;
     RECT  29.415 40.787 29.505 41.057 ;
     RECT  34.815 40.787 34.905 41.057 ;
     RECT  40.215 40.787 40.305 41.057 ;
     RECT  20.52 43.099 20.538 43.181 ;
     RECT  22.68 40.973 22.698 43.181 ;
    LAYER M4 ;
     RECT  0.025 10.128 0.06 10.152 ;
     RECT  0.06 2.256 0.569 40.968 ;
     RECT  0.569 2.256 2.408 28.44 ;
     RECT  0.569 29.952 2.408 32.328 ;
     RECT  0.569 33.36 2.408 40.968 ;
     RECT  2.408 2.148 2.512 41.052 ;
     RECT  2.512 2.352 2.704 40.968 ;
     RECT  2.704 2.352 2.765 7.752 ;
     RECT  2.765 2.352 3.665 7.176 ;
     RECT  3.665 3.36 4.025 7.176 ;
     RECT  2.704 8.832 4.025 28.44 ;
     RECT  4.025 3.36 4.061 5.688 ;
     RECT  4.061 4.128 4.169 5.688 ;
     RECT  4.025 6.816 4.345 7.176 ;
     RECT  4.345 6.816 4.403 7.464 ;
     RECT  4.403 7.44 4.429 7.464 ;
     RECT  4.169 4.752 4.529 5.688 ;
     RECT  4.025 9.648 4.529 28.44 ;
     RECT  4.529 9.696 5.393 28.44 ;
     RECT  4.529 4.752 5.42 4.776 ;
     RECT  4.345 2.256 5.429 2.28 ;
     RECT  5.42 4.512 5.507 4.776 ;
     RECT  5.461 8.112 5.573 8.136 ;
     RECT  5.507 4.752 5.609 4.776 ;
     RECT  5.713 2.784 7.808 2.808 ;
     RECT  5.677 8.16 7.808 8.184 ;
     RECT  5.393 10.176 7.808 28.44 ;
     RECT  2.704 29.904 7.808 32.328 ;
     RECT  2.704 33.36 7.808 40.968 ;
     RECT  7.808 2.148 7.912 41.052 ;
     RECT  7.912 2.418 8.104 40.968 ;
     RECT  8.104 8.16 13.208 8.184 ;
     RECT  8.104 10.176 13.208 28.44 ;
     RECT  8.104 29.904 13.208 32.328 ;
     RECT  8.104 33.36 13.208 40.968 ;
     RECT  13.208 2.148 13.312 41.052 ;
     RECT  13.312 2.418 13.504 40.968 ;
     RECT  13.504 10.176 13.961 28.44 ;
     RECT  13.961 10.176 14.861 11.4 ;
     RECT  13.504 33.36 17.093 40.968 ;
     RECT  13.504 8.16 18.608 8.184 ;
     RECT  14.861 10.176 18.608 11.256 ;
     RECT  13.961 12.48 18.608 28.44 ;
     RECT  13.504 29.904 18.608 32.328 ;
     RECT  17.093 33.36 18.608 34.152 ;
     RECT  17.093 35.424 18.608 40.968 ;
     RECT  18.608 2.148 18.712 41.052 ;
     RECT  18.712 2.418 18.904 40.968 ;
     RECT  18.904 33.552 18.965 34.152 ;
     RECT  18.904 10.176 19.397 11.256 ;
     RECT  18.904 35.424 19.397 40.968 ;
     RECT  18.904 17.664 19.433 28.44 ;
     RECT  18.965 33.552 19.433 33.576 ;
     RECT  19.433 22.56 19.469 28.44 ;
     RECT  19.469 23.088 19.613 28.44 ;
     RECT  19.433 17.664 19.649 21.24 ;
     RECT  19.613 23.088 19.685 24.456 ;
     RECT  19.613 25.488 19.685 27.48 ;
     RECT  19.685 25.488 19.757 27.192 ;
     RECT  19.685 23.664 19.829 24.456 ;
     RECT  19.649 19.584 19.865 21.24 ;
     RECT  19.757 25.488 19.865 27.096 ;
     RECT  19.865 19.872 19.901 21.24 ;
     RECT  19.865 25.488 19.901 26.376 ;
     RECT  19.649 17.664 19.937 18.024 ;
     RECT  19.397 36.576 19.973 40.968 ;
     RECT  19.973 36.576 20.225 40.728 ;
     RECT  20.225 39.6 20.261 40.728 ;
     RECT  19.397 35.424 20.513 35.448 ;
     RECT  20.261 39.888 20.513 40.728 ;
     RECT  20.513 40.56 20.549 40.728 ;
     RECT  20.492 43.104 20.579 43.128 ;
     RECT  20.225 36.576 20.693 38.472 ;
     RECT  20.533 22.08 20.797 22.2 ;
     RECT  20.693 36.576 21.089 36.84 ;
     RECT  19.901 19.872 21.121 20.856 ;
     RECT  20.797 22.08 21.121 22.536 ;
     RECT  19.397 10.176 21.125 11.16 ;
     RECT  18.904 12.48 21.125 16.68 ;
     RECT  21.125 10.176 21.155 10.968 ;
     RECT  19.901 25.488 21.197 25.512 ;
     RECT  21.121 19.872 21.233 22.536 ;
     RECT  21.233 19.872 21.269 19.896 ;
     RECT  18.904 30.864 21.341 32.04 ;
     RECT  19.937 18 21.377 18.024 ;
     RECT  21.341 30.864 21.449 30.888 ;
     RECT  20.549 40.56 21.485 40.584 ;
     RECT  21.125 12.48 21.491 16.296 ;
     RECT  21.373 19.536 21.491 19.56 ;
     RECT  21.491 12.768 21.521 16.296 ;
     RECT  21.521 15.504 21.539 16.296 ;
     RECT  21.341 32.016 21.557 32.04 ;
     RECT  20.693 37.92 21.557 38.472 ;
     RECT  21.539 15.6 21.593 16.296 ;
     RECT  19.829 23.664 21.593 23.688 ;
     RECT  21.521 12.768 21.665 14.232 ;
     RECT  21.089 36.816 21.665 36.84 ;
     RECT  21.557 37.92 21.665 37.944 ;
     RECT  21.553 19.44 21.697 19.464 ;
     RECT  21.665 14.208 21.737 14.232 ;
     RECT  21.697 18.768 21.737 19.464 ;
     RECT  21.665 12.768 21.773 12.792 ;
     RECT  21.737 18.768 21.809 18.792 ;
     RECT  21.233 21.264 21.841 22.536 ;
     RECT  21.155 10.416 21.953 10.968 ;
     RECT  21.593 15.696 21.989 16.296 ;
     RECT  21.841 21.264 22.097 22.776 ;
     RECT  21.953 10.416 22.169 10.44 ;
     RECT  21.989 16.272 22.169 16.296 ;
     RECT  21.841 40.416 22.273 40.44 ;
     RECT  22.273 40.32 22.313 40.44 ;
     RECT  23.353 15.072 23.605 15.672 ;
     RECT  22.097 21.264 23.641 22.536 ;
     RECT  18.904 8.16 24.008 8.184 ;
     RECT  23.605 14.928 24.008 15.672 ;
     RECT  23.641 21.264 24.008 22.632 ;
     RECT  23.605 25.2 24.008 25.224 ;
     RECT  22.313 40.32 24.008 40.344 ;
     RECT  24.008 2.148 24.112 41.052 ;
     RECT  24.112 2.418 24.304 40.782 ;
     RECT  24.304 25.2 26.345 25.224 ;
     RECT  26.737 25.44 27.635 25.464 ;
     RECT  27.589 30.816 27.781 30.84 ;
     RECT  24.304 40.32 27.781 40.344 ;
     RECT  27.781 30.816 27.827 30.936 ;
     RECT  27.781 39.36 27.865 40.344 ;
     RECT  24.304 14.928 29.408 14.952 ;
     RECT  27.827 30.912 29.408 30.936 ;
     RECT  27.865 39.456 29.408 40.344 ;
     RECT  29.408 2.148 29.512 41.052 ;
     RECT  29.512 2.418 29.704 40.782 ;
     RECT  29.704 30.816 30.809 30.936 ;
     RECT  33.073 22.656 33.257 22.68 ;
     RECT  29.704 39.36 33.347 39.384 ;
     RECT  33.109 40.56 33.347 40.584 ;
     RECT  33.301 35.28 33.797 35.304 ;
     RECT  30.809 30.912 34.549 30.936 ;
     RECT  29.704 14.928 34.765 14.952 ;
     RECT  34.693 10.992 34.808 11.016 ;
     RECT  34.585 13.296 34.808 13.32 ;
     RECT  34.765 14.928 34.808 15.48 ;
     RECT  34.261 17.088 34.808 17.112 ;
     RECT  34.117 21.504 34.808 21.528 ;
     RECT  33.829 24.48 34.808 25.704 ;
     RECT  34.333 27.888 34.808 27.912 ;
     RECT  34.549 30.912 34.808 31.416 ;
     RECT  34.117 38.16 34.808 38.184 ;
     RECT  34.808 2.148 34.912 41.052 ;
     RECT  34.912 2.418 35.104 40.782 ;
     RECT  35.104 13.536 35.219 13.56 ;
     RECT  35.104 26.928 35.219 29.592 ;
     RECT  35.104 35.424 35.245 36.408 ;
     RECT  35.245 35.424 35.267 35.976 ;
     RECT  35.104 33.36 35.309 33.624 ;
     RECT  35.219 27.312 35.381 29.592 ;
     RECT  35.104 17.088 35.417 17.112 ;
     RECT  35.104 30.816 35.489 31.416 ;
     RECT  35.104 37.632 35.489 38.184 ;
     RECT  35.104 20.544 35.525 23.928 ;
     RECT  35.525 20.544 35.705 23.544 ;
     RECT  35.489 30.816 35.741 30.936 ;
     RECT  35.104 10.992 35.813 11.304 ;
     RECT  35.381 28.8 35.884 29.592 ;
     RECT  35.705 22.176 35.891 23.544 ;
     RECT  35.104 12.528 36.097 12.552 ;
     RECT  35.104 25.2 36.137 25.224 ;
     RECT  35.104 39.888 36.137 39.912 ;
     RECT  35.309 33.6 36.173 33.624 ;
     RECT  35.104 14.928 36.277 16.008 ;
     RECT  35.267 35.952 36.349 35.976 ;
     RECT  35.741 30.816 36.385 30.84 ;
     RECT  35.884 29.568 36.493 29.592 ;
     RECT  36.385 30.768 36.497 30.84 ;
     RECT  36.493 29.568 36.533 29.688 ;
     RECT  35.489 38.16 36.533 38.184 ;
     RECT  36.349 35.04 36.713 35.976 ;
     RECT  35.104 19.152 36.773 19.176 ;
     RECT  36.277 14.88 36.781 16.008 ;
     RECT  36.773 18.816 36.781 19.176 ;
     RECT  35.705 20.544 36.781 20.568 ;
     RECT  36.781 18.816 36.857 20.568 ;
     RECT  35.891 22.752 36.961 23.544 ;
     RECT  36.961 22.704 36.997 23.544 ;
     RECT  36.853 39.456 36.997 39.48 ;
     RECT  36.097 11.952 37.043 12.552 ;
     RECT  36.709 13.776 37.069 13.8 ;
     RECT  37.043 12.528 37.109 12.552 ;
     RECT  36.997 22.704 37.177 23.688 ;
     RECT  36.997 38.784 37.181 39.48 ;
     RECT  36.781 14.88 37.217 16.056 ;
     RECT  36.857 19.152 37.253 20.568 ;
     RECT  36.457 31.92 37.537 31.944 ;
     RECT  37.069 13.68 37.541 13.8 ;
     RECT  37.177 22.704 37.573 23.928 ;
     RECT  37.573 5.856 37.609 5.88 ;
     RECT  37.573 22.704 37.613 24.552 ;
     RECT  36.533 29.664 37.685 29.688 ;
     RECT  37.253 20.496 37.717 20.568 ;
     RECT  37.249 21.648 37.717 21.672 ;
     RECT  37.717 20.496 37.721 21.672 ;
     RECT  37.613 22.704 37.825 22.824 ;
     RECT  37.541 13.68 37.829 13.704 ;
     RECT  37.429 17.088 37.901 17.112 ;
     RECT  37.573 26.208 37.933 26.232 ;
     RECT  35.381 27.312 37.964 27.336 ;
     RECT  37.609 28.464 37.964 28.488 ;
     RECT  37.933 25.968 37.969 26.232 ;
     RECT  37.964 27.312 37.969 28.488 ;
     RECT  36.713 35.04 37.997 35.064 ;
     RECT  37.721 20.496 38.009 21.288 ;
     RECT  37.997 34.224 38.041 35.064 ;
     RECT  37.613 23.904 38.045 24.552 ;
     RECT  37.969 25.968 38.051 28.488 ;
     RECT  36.497 30.816 38.051 30.84 ;
     RECT  38.041 34.224 38.099 35.352 ;
     RECT  37.181 38.784 38.099 39.144 ;
     RECT  37.537 31.92 38.113 32.472 ;
     RECT  36.925 40.608 38.117 40.632 ;
     RECT  37.217 15.168 38.189 16.056 ;
     RECT  38.051 25.968 38.243 27.096 ;
     RECT  38.051 28.464 38.444 28.488 ;
     RECT  38.444 28.464 38.513 29.016 ;
     RECT  38.513 28.992 38.531 29.016 ;
     RECT  38.113 31.056 38.581 32.472 ;
     RECT  38.189 15.168 38.657 15.432 ;
     RECT  38.243 26.256 38.657 27.096 ;
     RECT  37.825 22.512 38.693 22.824 ;
     RECT  38.581 31.056 38.693 32.904 ;
     RECT  38.693 32.16 38.729 32.904 ;
     RECT  37.573 37.536 38.729 37.56 ;
     RECT  37.253 19.152 38.761 19.176 ;
     RECT  38.693 22.512 38.761 22.536 ;
     RECT  38.761 19.152 38.801 19.416 ;
     RECT  38.485 30 38.801 30.024 ;
     RECT  38.693 31.056 38.801 31.08 ;
     RECT  36.493 10.608 38.837 10.632 ;
     RECT  38.657 15.408 38.837 15.432 ;
     RECT  38.045 24.528 38.837 24.552 ;
     RECT  38.729 32.448 38.861 32.904 ;
     RECT  38.099 35.328 38.869 35.352 ;
     RECT  38.761 22.416 38.909 22.536 ;
     RECT  38.861 32.448 38.915 33.672 ;
     RECT  38.869 35.328 38.915 35.928 ;
     RECT  38.828 38.112 38.915 38.136 ;
     RECT  38.909 22.416 38.945 22.44 ;
     RECT  38.915 33.648 38.945 33.672 ;
     RECT  38.915 32.448 38.981 32.472 ;
     RECT  39.013 12.72 39.308 12.744 ;
     RECT  38.905 14.064 39.308 14.088 ;
     RECT  39.308 12.72 39.349 14.088 ;
     RECT  37.609 5.856 39.913 6.072 ;
     RECT  39.913 5.856 40.208 7.368 ;
     RECT  39.301 8.784 40.208 9 ;
     RECT  39.349 11.952 40.208 14.088 ;
     RECT  38.801 19.392 40.208 19.416 ;
     RECT  38.009 21.264 40.208 21.288 ;
     RECT  38.657 27.072 40.208 27.096 ;
     RECT  38.915 35.904 40.208 35.928 ;
     RECT  38.099 39.12 40.208 39.144 ;
     RECT  40.208 2.148 40.312 41.052 ;
     RECT  40.312 2.418 40.504 40.782 ;
     RECT  40.504 34.464 41.497 35.064 ;
     RECT  40.504 11.136 41.533 13.464 ;
     RECT  40.504 32.208 41.533 33 ;
     RECT  41.497 34.464 41.533 36.024 ;
     RECT  40.504 39.408 41.533 39.432 ;
     RECT  40.504 3.024 41.569 10.056 ;
     RECT  41.533 11.136 41.569 14.04 ;
     RECT  40.504 15.504 41.569 15.528 ;
     RECT  40.504 17.04 41.569 20.28 ;
     RECT  40.504 21.792 41.569 24.84 ;
     RECT  40.504 27.456 41.569 30.888 ;
     RECT  41.533 32.208 41.569 36.024 ;
     RECT  40.504 37.344 41.569 37.368 ;
     RECT  41.533 38.64 41.569 40.392 ;
     RECT  41.569 3.024 41.605 24.84 ;
     RECT  41.569 25.968 41.605 40.392 ;
     RECT  41.605 2.256 42.145 40.392 ;
     RECT  42.145 2.256 42.181 40.584 ;
     RECT  42.181 2.256 43.164 40.968 ;
    LAYER M5 ;
     RECT  2.4 2.137 2.52 2.151 ;
     RECT  7.8 2.137 7.92 2.151 ;
     RECT  13.2 2.137 13.32 2.151 ;
     RECT  18.6 2.137 18.72 2.151 ;
     RECT  24 2.137 24.12 2.151 ;
     RECT  29.4 2.137 29.52 2.151 ;
     RECT  34.8 2.137 34.92 2.151 ;
     RECT  40.2 2.137 40.32 2.151 ;
     RECT  4.368 5.653 4.392 7.475 ;
     RECT  5.472 4.501 5.496 8.147 ;
     RECT  24 2.151 24.312 8.149 ;
     RECT  2.4 2.151 2.712 8.821 ;
     RECT  2.256 8.821 2.712 9.011 ;
     RECT  34.8 2.151 35.112 10.981 ;
     RECT  40.2 2.151 40.512 11.941 ;
     RECT  21.12 10.165 21.144 12.469 ;
     RECT  37.008 11.941 37.032 13.765 ;
     RECT  36.72 13.765 37.032 13.811 ;
     RECT  39.36 11.941 40.512 14.099 ;
     RECT  34.8 10.981 35.208 15.013 ;
     RECT  36.72 13.811 36.744 15.013 ;
     RECT  23.616 8.149 24.312 15.061 ;
     RECT  34.8 15.013 36.744 15.349 ;
     RECT  21.12 12.469 21.48 15.493 ;
     RECT  21.12 15.493 21.528 15.635 ;
     RECT  34.8 15.349 36.84 16.019 ;
     RECT  36.816 16.019 36.84 18.851 ;
     RECT  21.12 15.635 21.48 19.571 ;
     RECT  21.12 19.571 21.192 20.003 ;
     RECT  21.168 20.003 21.192 21.779 ;
     RECT  34.8 16.019 35.112 22.165 ;
     RECT  23.376 15.061 24.312 22.211 ;
     RECT  34.8 22.165 35.88 23.027 ;
     RECT  34.8 23.027 35.496 24.469 ;
     RECT  38.016 22.741 38.04 24.517 ;
     RECT  23.616 22.211 24.312 25.235 ;
     RECT  33.84 24.469 35.496 25.235 ;
     RECT  33.84 25.235 35.112 25.715 ;
     RECT  38.016 24.517 38.232 26.291 ;
     RECT  34.8 25.715 35.112 26.917 ;
     RECT  34.8 26.917 35.208 28.789 ;
     RECT  38.016 26.291 38.04 28.981 ;
     RECT  34.8 28.789 35.832 29.603 ;
     RECT  38.016 28.981 38.52 30.035 ;
     RECT  27.6 25.429 27.624 30.805 ;
     RECT  27.6 30.805 27.816 30.851 ;
     RECT  38.016 30.035 38.04 32.437 ;
     RECT  34.8 29.603 35.112 33.349 ;
     RECT  38.016 32.437 38.904 33.683 ;
     RECT  38.016 33.683 38.088 34.259 ;
     RECT  38.064 34.259 38.088 35.317 ;
     RECT  34.8 33.349 35.256 35.459 ;
     RECT  38.064 35.317 38.904 35.939 ;
     RECT  36.432 35.029 36.456 35.987 ;
     RECT  34.8 35.459 35.208 37.667 ;
     RECT  38.064 35.939 38.088 38.101 ;
     RECT  38.064 38.101 38.904 38.819 ;
     RECT  38.88 38.819 38.904 39.155 ;
     RECT  27.792 30.851 27.816 39.395 ;
     RECT  29.4 2.151 29.712 39.445 ;
     RECT  28.464 39.445 29.712 40.355 ;
     RECT  33.312 35.269 33.336 40.595 ;
     RECT  2.4 9.011 2.712 41.049 ;
     RECT  7.8 2.151 8.112 41.049 ;
     RECT  13.2 2.151 13.512 41.049 ;
     RECT  18.6 2.151 18.912 41.049 ;
     RECT  24 25.235 24.312 41.049 ;
     RECT  29.4 40.355 29.712 41.049 ;
     RECT  34.8 37.667 35.112 41.049 ;
     RECT  40.2 14.099 40.512 41.049 ;
     RECT  2.4 41.049 2.52 41.063 ;
     RECT  7.8 41.049 7.92 41.063 ;
     RECT  13.2 41.049 13.32 41.063 ;
     RECT  18.6 41.049 18.72 41.063 ;
     RECT  24 41.049 24.12 41.063 ;
     RECT  29.4 41.049 29.52 41.063 ;
     RECT  34.8 41.049 34.92 41.063 ;
     RECT  40.2 41.049 40.32 41.063 ;
     RECT  20.544 22.165 20.568 43.139 ;
  END
END ot_hbm_su_stree_leaf
END LIBRARY
